VERSION 5.8 ;
BUSBITCHARS "[]" ;
DIVIDERCHAR "/" ;
UNITS
    DATABASE MICRONS 1000 ;
END UNITS

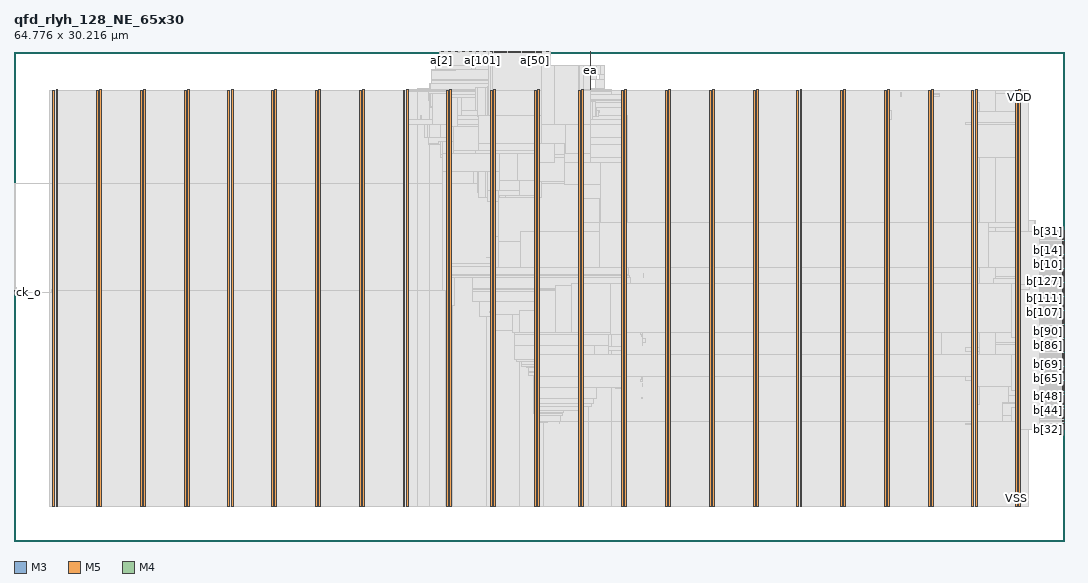
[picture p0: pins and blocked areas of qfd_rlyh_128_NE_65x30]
MACRO qfd_rlyh_128_NE_65x30
  FOREIGN qfd_rlyh_128_NE_65x30 0 0 ;
  CLASS BLOCK ;
  SIZE 64.776 BY 30.216 ;
  PIN a[0]
    DIRECTION INPUT ;
    USE SIGNAL ;
    PORT
      LAYER M3 ;
        RECT  26.244 30.179 26.262 30.216 ;
    END
  END a[0]
  PIN a[100]
    DIRECTION INPUT ;
    USE SIGNAL ;
    PORT
      LAYER M3 ;
        RECT  28.836 30.179 28.854 30.216 ;
    END
  END a[100]
  PIN a[101]
    DIRECTION INPUT ;
    USE SIGNAL ;
    PORT
      LAYER M3 ;
        RECT  28.908 30.179 28.926 30.216 ;
    END
  END a[101]
  PIN a[102]
    DIRECTION INPUT ;
    USE SIGNAL ;
    PORT
      LAYER M3 ;
        RECT  28.98 30.179 28.998 30.216 ;
    END
  END a[102]
  PIN a[103]
    DIRECTION INPUT ;
    USE SIGNAL ;
    PORT
      LAYER M3 ;
        RECT  29.052 30.179 29.07 30.216 ;
    END
  END a[103]
  PIN a[104]
    DIRECTION INPUT ;
    USE SIGNAL ;
    PORT
      LAYER M3 ;
        RECT  29.124 30.179 29.142 30.216 ;
    END
  END a[104]
  PIN a[105]
    DIRECTION INPUT ;
    USE SIGNAL ;
    PORT
      LAYER M3 ;
        RECT  29.196 30.179 29.214 30.216 ;
    END
  END a[105]
  PIN a[106]
    DIRECTION INPUT ;
    USE SIGNAL ;
    PORT
      LAYER M3 ;
        RECT  29.268 30.179 29.286 30.216 ;
    END
  END a[106]
  PIN a[107]
    DIRECTION INPUT ;
    USE SIGNAL ;
    PORT
      LAYER M3 ;
        RECT  29.34 30.179 29.358 30.216 ;
    END
  END a[107]
  PIN a[108]
    DIRECTION INPUT ;
    USE SIGNAL ;
    PORT
      LAYER M3 ;
        RECT  29.412 30.179 29.43 30.216 ;
    END
  END a[108]
  PIN a[109]
    DIRECTION INPUT ;
    USE SIGNAL ;
    PORT
      LAYER M3 ;
        RECT  29.484 30.179 29.502 30.216 ;
    END
  END a[109]
  PIN a[10]
    DIRECTION INPUT ;
    USE SIGNAL ;
    PORT
      LAYER M3 ;
        RECT  26.964 30.179 26.982 30.216 ;
    END
  END a[10]
  PIN a[110]
    DIRECTION INPUT ;
    USE SIGNAL ;
    PORT
      LAYER M3 ;
        RECT  29.556 30.179 29.574 30.216 ;
    END
  END a[110]
  PIN a[111]
    DIRECTION INPUT ;
    USE SIGNAL ;
    PORT
      LAYER M3 ;
        RECT  29.628 30.179 29.646 30.216 ;
    END
  END a[111]
  PIN a[112]
    DIRECTION INPUT ;
    USE SIGNAL ;
    PORT
      LAYER M3 ;
        RECT  29.7 30.179 29.718 30.216 ;
    END
  END a[112]
  PIN a[113]
    DIRECTION INPUT ;
    USE SIGNAL ;
    PORT
      LAYER M3 ;
        RECT  29.772 30.179 29.79 30.216 ;
    END
  END a[113]
  PIN a[114]
    DIRECTION INPUT ;
    USE SIGNAL ;
    PORT
      LAYER M3 ;
        RECT  29.844 30.179 29.862 30.216 ;
    END
  END a[114]
  PIN a[115]
    DIRECTION INPUT ;
    USE SIGNAL ;
    PORT
      LAYER M3 ;
        RECT  29.916 30.179 29.934 30.216 ;
    END
  END a[115]
  PIN a[116]
    DIRECTION INPUT ;
    USE SIGNAL ;
    PORT
      LAYER M3 ;
        RECT  29.988 30.179 30.006 30.216 ;
    END
  END a[116]
  PIN a[117]
    DIRECTION INPUT ;
    USE SIGNAL ;
    PORT
      LAYER M3 ;
        RECT  30.06 30.179 30.078 30.216 ;
    END
  END a[117]
  PIN a[118]
    DIRECTION INPUT ;
    USE SIGNAL ;
    PORT
      LAYER M3 ;
        RECT  30.132 30.179 30.15 30.216 ;
    END
  END a[118]
  PIN a[119]
    DIRECTION INPUT ;
    USE SIGNAL ;
    PORT
      LAYER M3 ;
        RECT  30.204 30.179 30.222 30.216 ;
    END
  END a[119]
  PIN a[11]
    DIRECTION INPUT ;
    USE SIGNAL ;
    PORT
      LAYER M3 ;
        RECT  27.036 30.179 27.054 30.216 ;
    END
  END a[11]
  PIN a[120]
    DIRECTION INPUT ;
    USE SIGNAL ;
    PORT
      LAYER M3 ;
        RECT  30.276 30.179 30.294 30.216 ;
    END
  END a[120]
  PIN a[121]
    DIRECTION INPUT ;
    USE SIGNAL ;
    PORT
      LAYER M3 ;
        RECT  30.348 30.179 30.366 30.216 ;
    END
  END a[121]
  PIN a[122]
    DIRECTION INPUT ;
    USE SIGNAL ;
    PORT
      LAYER M3 ;
        RECT  30.42 30.179 30.438 30.216 ;
    END
  END a[122]
  PIN a[123]
    DIRECTION INPUT ;
    USE SIGNAL ;
    PORT
      LAYER M3 ;
        RECT  30.492 30.179 30.51 30.216 ;
    END
  END a[123]
  PIN a[124]
    DIRECTION INPUT ;
    USE SIGNAL ;
    PORT
      LAYER M3 ;
        RECT  30.564 30.179 30.582 30.216 ;
    END
  END a[124]
  PIN a[125]
    DIRECTION INPUT ;
    USE SIGNAL ;
    PORT
      LAYER M3 ;
        RECT  30.636 30.179 30.654 30.216 ;
    END
  END a[125]
  PIN a[126]
    DIRECTION INPUT ;
    USE SIGNAL ;
    PORT
      LAYER M3 ;
        RECT  30.708 30.179 30.726 30.216 ;
    END
  END a[126]
  PIN a[127]
    DIRECTION INPUT ;
    USE SIGNAL ;
    PORT
      LAYER M3 ;
        RECT  30.78 30.179 30.798 30.216 ;
    END
  END a[127]
  PIN a[12]
    DIRECTION INPUT ;
    USE SIGNAL ;
    PORT
      LAYER M3 ;
        RECT  27.108 30.179 27.126 30.216 ;
    END
  END a[12]
  PIN a[13]
    DIRECTION INPUT ;
    USE SIGNAL ;
    PORT
      LAYER M3 ;
        RECT  27.18 30.179 27.198 30.216 ;
    END
  END a[13]
  PIN a[14]
    DIRECTION INPUT ;
    USE SIGNAL ;
    PORT
      LAYER M3 ;
        RECT  27.252 30.179 27.27 30.216 ;
    END
  END a[14]
  PIN a[15]
    DIRECTION INPUT ;
    USE SIGNAL ;
    PORT
      LAYER M3 ;
        RECT  27.324 30.179 27.342 30.216 ;
    END
  END a[15]
  PIN a[16]
    DIRECTION INPUT ;
    USE SIGNAL ;
    PORT
      LAYER M3 ;
        RECT  27.396 30.179 27.414 30.216 ;
    END
  END a[16]
  PIN a[17]
    DIRECTION INPUT ;
    USE SIGNAL ;
    PORT
      LAYER M3 ;
        RECT  27.468 30.179 27.486 30.216 ;
    END
  END a[17]
  PIN a[18]
    DIRECTION INPUT ;
    USE SIGNAL ;
    PORT
      LAYER M3 ;
        RECT  27.54 30.179 27.558 30.216 ;
    END
  END a[18]
  PIN a[19]
    DIRECTION INPUT ;
    USE SIGNAL ;
    PORT
      LAYER M3 ;
        RECT  27.612 30.179 27.63 30.216 ;
    END
  END a[19]
  PIN a[1]
    DIRECTION INPUT ;
    USE SIGNAL ;
    PORT
      LAYER M3 ;
        RECT  26.316 30.179 26.334 30.216 ;
    END
  END a[1]
  PIN a[20]
    DIRECTION INPUT ;
    USE SIGNAL ;
    PORT
      LAYER M3 ;
        RECT  27.684 30.179 27.702 30.216 ;
    END
  END a[20]
  PIN a[21]
    DIRECTION INPUT ;
    USE SIGNAL ;
    PORT
      LAYER M3 ;
        RECT  27.756 30.179 27.774 30.216 ;
    END
  END a[21]
  PIN a[22]
    DIRECTION INPUT ;
    USE SIGNAL ;
    PORT
      LAYER M3 ;
        RECT  27.828 30.179 27.846 30.216 ;
    END
  END a[22]
  PIN a[23]
    DIRECTION INPUT ;
    USE SIGNAL ;
    PORT
      LAYER M3 ;
        RECT  27.9 30.179 27.918 30.216 ;
    END
  END a[23]
  PIN a[24]
    DIRECTION INPUT ;
    USE SIGNAL ;
    PORT
      LAYER M3 ;
        RECT  27.972 30.179 27.99 30.216 ;
    END
  END a[24]
  PIN a[25]
    DIRECTION INPUT ;
    USE SIGNAL ;
    PORT
      LAYER M3 ;
        RECT  28.044 30.179 28.062 30.216 ;
    END
  END a[25]
  PIN a[26]
    DIRECTION INPUT ;
    USE SIGNAL ;
    PORT
      LAYER M3 ;
        RECT  28.116 30.179 28.134 30.216 ;
    END
  END a[26]
  PIN a[27]
    DIRECTION INPUT ;
    USE SIGNAL ;
    PORT
      LAYER M3 ;
        RECT  28.188 30.179 28.206 30.216 ;
    END
  END a[27]
  PIN a[28]
    DIRECTION INPUT ;
    USE SIGNAL ;
    PORT
      LAYER M3 ;
        RECT  28.26 30.179 28.278 30.216 ;
    END
  END a[28]
  PIN a[29]
    DIRECTION INPUT ;
    USE SIGNAL ;
    PORT
      LAYER M3 ;
        RECT  28.332 30.179 28.35 30.216 ;
    END
  END a[29]
  PIN a[2]
    DIRECTION INPUT ;
    USE SIGNAL ;
    PORT
      LAYER M3 ;
        RECT  26.388 30.179 26.406 30.216 ;
    END
  END a[2]
  PIN a[30]
    DIRECTION INPUT ;
    USE SIGNAL ;
    PORT
      LAYER M3 ;
        RECT  28.404 30.179 28.422 30.216 ;
    END
  END a[30]
  PIN a[31]
    DIRECTION INPUT ;
    USE SIGNAL ;
    PORT
      LAYER M3 ;
        RECT  28.476 30.179 28.494 30.216 ;
    END
  END a[31]
  PIN a[32]
    DIRECTION INPUT ;
    USE SIGNAL ;
    PORT
      LAYER M3 ;
        RECT  30.852 30.179 30.87 30.216 ;
    END
  END a[32]
  PIN a[33]
    DIRECTION INPUT ;
    USE SIGNAL ;
    PORT
      LAYER M3 ;
        RECT  30.924 30.179 30.942 30.216 ;
    END
  END a[33]
  PIN a[34]
    DIRECTION INPUT ;
    USE SIGNAL ;
    PORT
      LAYER M3 ;
        RECT  30.996 30.179 31.014 30.216 ;
    END
  END a[34]
  PIN a[35]
    DIRECTION INPUT ;
    USE SIGNAL ;
    PORT
      LAYER M3 ;
        RECT  31.068 30.179 31.086 30.216 ;
    END
  END a[35]
  PIN a[36]
    DIRECTION INPUT ;
    USE SIGNAL ;
    PORT
      LAYER M3 ;
        RECT  31.14 30.179 31.158 30.216 ;
    END
  END a[36]
  PIN a[37]
    DIRECTION INPUT ;
    USE SIGNAL ;
    PORT
      LAYER M3 ;
        RECT  31.212 30.179 31.23 30.216 ;
    END
  END a[37]
  PIN a[38]
    DIRECTION INPUT ;
    USE SIGNAL ;
    PORT
      LAYER M3 ;
        RECT  31.284 30.179 31.302 30.216 ;
    END
  END a[38]
  PIN a[39]
    DIRECTION INPUT ;
    USE SIGNAL ;
    PORT
      LAYER M3 ;
        RECT  31.356 30.179 31.374 30.216 ;
    END
  END a[39]
  PIN a[3]
    DIRECTION INPUT ;
    USE SIGNAL ;
    PORT
      LAYER M3 ;
        RECT  26.46 30.179 26.478 30.216 ;
    END
  END a[3]
  PIN a[40]
    DIRECTION INPUT ;
    USE SIGNAL ;
    PORT
      LAYER M3 ;
        RECT  31.428 30.179 31.446 30.216 ;
    END
  END a[40]
  PIN a[41]
    DIRECTION INPUT ;
    USE SIGNAL ;
    PORT
      LAYER M3 ;
        RECT  31.5 30.179 31.518 30.216 ;
    END
  END a[41]
  PIN a[42]
    DIRECTION INPUT ;
    USE SIGNAL ;
    PORT
      LAYER M3 ;
        RECT  31.572 30.179 31.59 30.216 ;
    END
  END a[42]
  PIN a[43]
    DIRECTION INPUT ;
    USE SIGNAL ;
    PORT
      LAYER M3 ;
        RECT  31.644 30.179 31.662 30.216 ;
    END
  END a[43]
  PIN a[44]
    DIRECTION INPUT ;
    USE SIGNAL ;
    PORT
      LAYER M3 ;
        RECT  31.716 30.179 31.734 30.216 ;
    END
  END a[44]
  PIN a[45]
    DIRECTION INPUT ;
    USE SIGNAL ;
    PORT
      LAYER M3 ;
        RECT  31.788 30.179 31.806 30.216 ;
    END
  END a[45]
  PIN a[46]
    DIRECTION INPUT ;
    USE SIGNAL ;
    PORT
      LAYER M3 ;
        RECT  31.86 30.179 31.878 30.216 ;
    END
  END a[46]
  PIN a[47]
    DIRECTION INPUT ;
    USE SIGNAL ;
    PORT
      LAYER M3 ;
        RECT  31.932 30.179 31.95 30.216 ;
    END
  END a[47]
  PIN a[48]
    DIRECTION INPUT ;
    USE SIGNAL ;
    PORT
      LAYER M3 ;
        RECT  32.004 30.179 32.022 30.216 ;
    END
  END a[48]
  PIN a[49]
    DIRECTION INPUT ;
    USE SIGNAL ;
    PORT
      LAYER M3 ;
        RECT  32.076 30.179 32.094 30.216 ;
    END
  END a[49]
  PIN a[4]
    DIRECTION INPUT ;
    USE SIGNAL ;
    PORT
      LAYER M3 ;
        RECT  26.532 30.179 26.55 30.216 ;
    END
  END a[4]
  PIN a[50]
    DIRECTION INPUT ;
    USE SIGNAL ;
    PORT
      LAYER M3 ;
        RECT  32.148 30.179 32.166 30.216 ;
    END
  END a[50]
  PIN a[51]
    DIRECTION INPUT ;
    USE SIGNAL ;
    PORT
      LAYER M3 ;
        RECT  32.22 30.179 32.238 30.216 ;
    END
  END a[51]
  PIN a[52]
    DIRECTION INPUT ;
    USE SIGNAL ;
    PORT
      LAYER M3 ;
        RECT  32.292 30.179 32.31 30.216 ;
    END
  END a[52]
  PIN a[53]
    DIRECTION INPUT ;
    USE SIGNAL ;
    PORT
      LAYER M3 ;
        RECT  32.364 30.179 32.382 30.216 ;
    END
  END a[53]
  PIN a[54]
    DIRECTION INPUT ;
    USE SIGNAL ;
    PORT
      LAYER M3 ;
        RECT  32.436 30.179 32.454 30.216 ;
    END
  END a[54]
  PIN a[55]
    DIRECTION INPUT ;
    USE SIGNAL ;
    PORT
      LAYER M3 ;
        RECT  32.508 30.179 32.526 30.216 ;
    END
  END a[55]
  PIN a[56]
    DIRECTION INPUT ;
    USE SIGNAL ;
    PORT
      LAYER M3 ;
        RECT  32.58 30.179 32.598 30.216 ;
    END
  END a[56]
  PIN a[57]
    DIRECTION INPUT ;
    USE SIGNAL ;
    PORT
      LAYER M3 ;
        RECT  32.652 30.179 32.67 30.216 ;
    END
  END a[57]
  PIN a[58]
    DIRECTION INPUT ;
    USE SIGNAL ;
    PORT
      LAYER M3 ;
        RECT  32.724 30.179 32.742 30.216 ;
    END
  END a[58]
  PIN a[59]
    DIRECTION INPUT ;
    USE SIGNAL ;
    PORT
      LAYER M3 ;
        RECT  32.796 30.179 32.814 30.216 ;
    END
  END a[59]
  PIN a[5]
    DIRECTION INPUT ;
    USE SIGNAL ;
    PORT
      LAYER M3 ;
        RECT  26.604 30.179 26.622 30.216 ;
    END
  END a[5]
  PIN a[60]
    DIRECTION INPUT ;
    USE SIGNAL ;
    PORT
      LAYER M3 ;
        RECT  32.868 30.179 32.886 30.216 ;
    END
  END a[60]
  PIN a[61]
    DIRECTION INPUT ;
    USE SIGNAL ;
    PORT
      LAYER M3 ;
        RECT  32.94 30.179 32.958 30.216 ;
    END
  END a[61]
  PIN a[62]
    DIRECTION INPUT ;
    USE SIGNAL ;
    PORT
      LAYER M3 ;
        RECT  33.012 30.179 33.03 30.216 ;
    END
  END a[62]
  PIN a[63]
    DIRECTION INPUT ;
    USE SIGNAL ;
    PORT
      LAYER M3 ;
        RECT  33.084 30.179 33.102 30.216 ;
    END
  END a[63]
  PIN a[64]
    DIRECTION INPUT ;
    USE SIGNAL ;
    PORT
      LAYER M5 ;
        RECT  29.52 30.132 29.544 30.216 ;
    END
  END a[64]
  PIN a[65]
    DIRECTION INPUT ;
    USE SIGNAL ;
    PORT
      LAYER M5 ;
        RECT  29.616 30.132 29.64 30.216 ;
    END
  END a[65]
  PIN a[66]
    DIRECTION INPUT ;
    USE SIGNAL ;
    PORT
      LAYER M5 ;
        RECT  29.712 30.132 29.736 30.216 ;
    END
  END a[66]
  PIN a[67]
    DIRECTION INPUT ;
    USE SIGNAL ;
    PORT
      LAYER M5 ;
        RECT  29.808 30.132 29.832 30.216 ;
    END
  END a[67]
  PIN a[68]
    DIRECTION INPUT ;
    USE SIGNAL ;
    PORT
      LAYER M5 ;
        RECT  29.904 30.132 29.928 30.216 ;
    END
  END a[68]
  PIN a[69]
    DIRECTION INPUT ;
    USE SIGNAL ;
    PORT
      LAYER M5 ;
        RECT  30 30.132 30.024 30.216 ;
    END
  END a[69]
  PIN a[6]
    DIRECTION INPUT ;
    USE SIGNAL ;
    PORT
      LAYER M3 ;
        RECT  26.676 30.179 26.694 30.216 ;
    END
  END a[6]
  PIN a[70]
    DIRECTION INPUT ;
    USE SIGNAL ;
    PORT
      LAYER M5 ;
        RECT  30.096 30.132 30.12 30.216 ;
    END
  END a[70]
  PIN a[71]
    DIRECTION INPUT ;
    USE SIGNAL ;
    PORT
      LAYER M5 ;
        RECT  30.192 30.132 30.216 30.216 ;
    END
  END a[71]
  PIN a[72]
    DIRECTION INPUT ;
    USE SIGNAL ;
    PORT
      LAYER M5 ;
        RECT  30.288 30.132 30.312 30.216 ;
    END
  END a[72]
  PIN a[73]
    DIRECTION INPUT ;
    USE SIGNAL ;
    PORT
      LAYER M5 ;
        RECT  30.384 30.132 30.408 30.216 ;
    END
  END a[73]
  PIN a[74]
    DIRECTION INPUT ;
    USE SIGNAL ;
    PORT
      LAYER M5 ;
        RECT  30.48 30.132 30.504 30.216 ;
    END
  END a[74]
  PIN a[75]
    DIRECTION INPUT ;
    USE SIGNAL ;
    PORT
      LAYER M5 ;
        RECT  30.576 30.132 30.6 30.216 ;
    END
  END a[75]
  PIN a[76]
    DIRECTION INPUT ;
    USE SIGNAL ;
    PORT
      LAYER M5 ;
        RECT  30.672 30.132 30.696 30.216 ;
    END
  END a[76]
  PIN a[77]
    DIRECTION INPUT ;
    USE SIGNAL ;
    PORT
      LAYER M5 ;
        RECT  30.768 30.132 30.792 30.216 ;
    END
  END a[77]
  PIN a[78]
    DIRECTION INPUT ;
    USE SIGNAL ;
    PORT
      LAYER M5 ;
        RECT  30.864 30.132 30.888 30.216 ;
    END
  END a[78]
  PIN a[79]
    DIRECTION INPUT ;
    USE SIGNAL ;
    PORT
      LAYER M5 ;
        RECT  30.96 30.132 30.984 30.216 ;
    END
  END a[79]
  PIN a[7]
    DIRECTION INPUT ;
    USE SIGNAL ;
    PORT
      LAYER M3 ;
        RECT  26.748 30.179 26.766 30.216 ;
    END
  END a[7]
  PIN a[80]
    DIRECTION INPUT ;
    USE SIGNAL ;
    PORT
      LAYER M5 ;
        RECT  31.056 30.132 31.08 30.216 ;
    END
  END a[80]
  PIN a[81]
    DIRECTION INPUT ;
    USE SIGNAL ;
    PORT
      LAYER M5 ;
        RECT  31.152 30.132 31.176 30.216 ;
    END
  END a[81]
  PIN a[82]
    DIRECTION INPUT ;
    USE SIGNAL ;
    PORT
      LAYER M5 ;
        RECT  31.248 30.132 31.272 30.216 ;
    END
  END a[82]
  PIN a[83]
    DIRECTION INPUT ;
    USE SIGNAL ;
    PORT
      LAYER M5 ;
        RECT  31.344 30.132 31.368 30.216 ;
    END
  END a[83]
  PIN a[84]
    DIRECTION INPUT ;
    USE SIGNAL ;
    PORT
      LAYER M5 ;
        RECT  31.44 30.132 31.464 30.216 ;
    END
  END a[84]
  PIN a[85]
    DIRECTION INPUT ;
    USE SIGNAL ;
    PORT
      LAYER M5 ;
        RECT  31.536 30.132 31.56 30.216 ;
    END
  END a[85]
  PIN a[86]
    DIRECTION INPUT ;
    USE SIGNAL ;
    PORT
      LAYER M5 ;
        RECT  31.632 30.132 31.656 30.216 ;
    END
  END a[86]
  PIN a[87]
    DIRECTION INPUT ;
    USE SIGNAL ;
    PORT
      LAYER M5 ;
        RECT  31.728 30.132 31.752 30.216 ;
    END
  END a[87]
  PIN a[88]
    DIRECTION INPUT ;
    USE SIGNAL ;
    PORT
      LAYER M5 ;
        RECT  31.824 30.132 31.848 30.216 ;
    END
  END a[88]
  PIN a[89]
    DIRECTION INPUT ;
    USE SIGNAL ;
    PORT
      LAYER M5 ;
        RECT  31.92 30.132 31.944 30.216 ;
    END
  END a[89]
  PIN a[8]
    DIRECTION INPUT ;
    USE SIGNAL ;
    PORT
      LAYER M3 ;
        RECT  26.82 30.179 26.838 30.216 ;
    END
  END a[8]
  PIN a[90]
    DIRECTION INPUT ;
    USE SIGNAL ;
    PORT
      LAYER M5 ;
        RECT  32.016 30.132 32.04 30.216 ;
    END
  END a[90]
  PIN a[91]
    DIRECTION INPUT ;
    USE SIGNAL ;
    PORT
      LAYER M5 ;
        RECT  32.112 30.132 32.136 30.216 ;
    END
  END a[91]
  PIN a[92]
    DIRECTION INPUT ;
    USE SIGNAL ;
    PORT
      LAYER M5 ;
        RECT  32.208 30.132 32.232 30.216 ;
    END
  END a[92]
  PIN a[93]
    DIRECTION INPUT ;
    USE SIGNAL ;
    PORT
      LAYER M5 ;
        RECT  32.304 30.132 32.328 30.216 ;
    END
  END a[93]
  PIN a[94]
    DIRECTION INPUT ;
    USE SIGNAL ;
    PORT
      LAYER M5 ;
        RECT  32.4 30.132 32.424 30.216 ;
    END
  END a[94]
  PIN a[95]
    DIRECTION INPUT ;
    USE SIGNAL ;
    PORT
      LAYER M5 ;
        RECT  32.496 30.132 32.52 30.216 ;
    END
  END a[95]
  PIN a[96]
    DIRECTION INPUT ;
    USE SIGNAL ;
    PORT
      LAYER M3 ;
        RECT  28.548 30.179 28.566 30.216 ;
    END
  END a[96]
  PIN a[97]
    DIRECTION INPUT ;
    USE SIGNAL ;
    PORT
      LAYER M3 ;
        RECT  28.62 30.179 28.638 30.216 ;
    END
  END a[97]
  PIN a[98]
    DIRECTION INPUT ;
    USE SIGNAL ;
    PORT
      LAYER M3 ;
        RECT  28.692 30.179 28.71 30.216 ;
    END
  END a[98]
  PIN a[99]
    DIRECTION INPUT ;
    USE SIGNAL ;
    PORT
      LAYER M3 ;
        RECT  28.764 30.179 28.782 30.216 ;
    END
  END a[99]
  PIN a[9]
    DIRECTION INPUT ;
    USE SIGNAL ;
    PORT
      LAYER M3 ;
        RECT  26.892 30.179 26.91 30.216 ;
    END
  END a[9]
  PIN b[0]
    DIRECTION OUTPUT ;
    USE SIGNAL ;
    PORT
      LAYER M4 ;
        RECT  64.692 16.08 64.776 16.104 ;
    END
  END b[0]
  PIN b[100]
    DIRECTION OUTPUT ;
    USE SIGNAL ;
    PORT
      LAYER M4 ;
        RECT  64.692 13.392 64.776 13.416 ;
    END
  END b[100]
  PIN b[101]
    DIRECTION OUTPUT ;
    USE SIGNAL ;
    PORT
      LAYER M4 ;
        RECT  64.692 13.488 64.776 13.512 ;
    END
  END b[101]
  PIN b[102]
    DIRECTION OUTPUT ;
    USE SIGNAL ;
    PORT
      LAYER M4 ;
        RECT  64.692 13.584 64.776 13.608 ;
    END
  END b[102]
  PIN b[103]
    DIRECTION OUTPUT ;
    USE SIGNAL ;
    PORT
      LAYER M4 ;
        RECT  64.692 13.68 64.776 13.704 ;
    END
  END b[103]
  PIN b[104]
    DIRECTION OUTPUT ;
    USE SIGNAL ;
    PORT
      LAYER M4 ;
        RECT  64.692 13.776 64.776 13.8 ;
    END
  END b[104]
  PIN b[105]
    DIRECTION OUTPUT ;
    USE SIGNAL ;
    PORT
      LAYER M4 ;
        RECT  64.692 13.872 64.776 13.896 ;
    END
  END b[105]
  PIN b[106]
    DIRECTION OUTPUT ;
    USE SIGNAL ;
    PORT
      LAYER M4 ;
        RECT  64.692 13.968 64.776 13.992 ;
    END
  END b[106]
  PIN b[107]
    DIRECTION OUTPUT ;
    USE SIGNAL ;
    PORT
      LAYER M4 ;
        RECT  64.692 14.064 64.776 14.088 ;
    END
  END b[107]
  PIN b[108]
    DIRECTION OUTPUT ;
    USE SIGNAL ;
    PORT
      LAYER M4 ;
        RECT  64.692 14.16 64.776 14.184 ;
    END
  END b[108]
  PIN b[109]
    DIRECTION OUTPUT ;
    USE SIGNAL ;
    PORT
      LAYER M4 ;
        RECT  64.692 14.256 64.776 14.28 ;
    END
  END b[109]
  PIN b[10]
    DIRECTION OUTPUT ;
    USE SIGNAL ;
    PORT
      LAYER M4 ;
        RECT  64.692 17.04 64.776 17.064 ;
    END
  END b[10]
  PIN b[110]
    DIRECTION OUTPUT ;
    USE SIGNAL ;
    PORT
      LAYER M4 ;
        RECT  64.692 14.352 64.776 14.376 ;
    END
  END b[110]
  PIN b[111]
    DIRECTION OUTPUT ;
    USE SIGNAL ;
    PORT
      LAYER M4 ;
        RECT  64.692 14.448 64.776 14.472 ;
    END
  END b[111]
  PIN b[112]
    DIRECTION OUTPUT ;
    USE SIGNAL ;
    PORT
      LAYER M4 ;
        RECT  64.692 14.544 64.776 14.568 ;
    END
  END b[112]
  PIN b[113]
    DIRECTION OUTPUT ;
    USE SIGNAL ;
    PORT
      LAYER M4 ;
        RECT  64.692 14.64 64.776 14.664 ;
    END
  END b[113]
  PIN b[114]
    DIRECTION OUTPUT ;
    USE SIGNAL ;
    PORT
      LAYER M4 ;
        RECT  64.692 14.736 64.776 14.76 ;
    END
  END b[114]
  PIN b[115]
    DIRECTION OUTPUT ;
    USE SIGNAL ;
    PORT
      LAYER M4 ;
        RECT  64.692 14.832 64.776 14.856 ;
    END
  END b[115]
  PIN b[116]
    DIRECTION OUTPUT ;
    USE SIGNAL ;
    PORT
      LAYER M4 ;
        RECT  64.692 14.928 64.776 14.952 ;
    END
  END b[116]
  PIN b[117]
    DIRECTION OUTPUT ;
    USE SIGNAL ;
    PORT
      LAYER M4 ;
        RECT  64.692 15.024 64.776 15.048 ;
    END
  END b[117]
  PIN b[118]
    DIRECTION OUTPUT ;
    USE SIGNAL ;
    PORT
      LAYER M4 ;
        RECT  64.692 15.12 64.776 15.144 ;
    END
  END b[118]
  PIN b[119]
    DIRECTION OUTPUT ;
    USE SIGNAL ;
    PORT
      LAYER M4 ;
        RECT  64.692 15.216 64.776 15.24 ;
    END
  END b[119]
  PIN b[11]
    DIRECTION OUTPUT ;
    USE SIGNAL ;
    PORT
      LAYER M4 ;
        RECT  64.692 17.136 64.776 17.16 ;
    END
  END b[11]
  PIN b[120]
    DIRECTION OUTPUT ;
    USE SIGNAL ;
    PORT
      LAYER M4 ;
        RECT  64.692 15.312 64.776 15.336 ;
    END
  END b[120]
  PIN b[121]
    DIRECTION OUTPUT ;
    USE SIGNAL ;
    PORT
      LAYER M4 ;
        RECT  64.692 15.408 64.776 15.432 ;
    END
  END b[121]
  PIN b[122]
    DIRECTION OUTPUT ;
    USE SIGNAL ;
    PORT
      LAYER M4 ;
        RECT  64.692 15.504 64.776 15.528 ;
    END
  END b[122]
  PIN b[123]
    DIRECTION OUTPUT ;
    USE SIGNAL ;
    PORT
      LAYER M4 ;
        RECT  64.692 15.6 64.776 15.624 ;
    END
  END b[123]
  PIN b[124]
    DIRECTION OUTPUT ;
    USE SIGNAL ;
    PORT
      LAYER M4 ;
        RECT  64.692 15.696 64.776 15.72 ;
    END
  END b[124]
  PIN b[125]
    DIRECTION OUTPUT ;
    USE SIGNAL ;
    PORT
      LAYER M4 ;
        RECT  64.692 15.792 64.776 15.816 ;
    END
  END b[125]
  PIN b[126]
    DIRECTION OUTPUT ;
    USE SIGNAL ;
    PORT
      LAYER M4 ;
        RECT  64.692 15.888 64.776 15.912 ;
    END
  END b[126]
  PIN b[127]
    DIRECTION OUTPUT ;
    USE SIGNAL ;
    PORT
      LAYER M4 ;
        RECT  64.692 15.984 64.776 16.008 ;
    END
  END b[127]
  PIN b[12]
    DIRECTION OUTPUT ;
    USE SIGNAL ;
    PORT
      LAYER M4 ;
        RECT  64.692 17.232 64.776 17.256 ;
    END
  END b[12]
  PIN b[13]
    DIRECTION OUTPUT ;
    USE SIGNAL ;
    PORT
      LAYER M4 ;
        RECT  64.692 17.328 64.776 17.352 ;
    END
  END b[13]
  PIN b[14]
    DIRECTION OUTPUT ;
    USE SIGNAL ;
    PORT
      LAYER M4 ;
        RECT  64.692 17.424 64.776 17.448 ;
    END
  END b[14]
  PIN b[15]
    DIRECTION OUTPUT ;
    USE SIGNAL ;
    PORT
      LAYER M4 ;
        RECT  64.692 17.52 64.776 17.544 ;
    END
  END b[15]
  PIN b[16]
    DIRECTION OUTPUT ;
    USE SIGNAL ;
    PORT
      LAYER M4 ;
        RECT  64.692 17.616 64.776 17.64 ;
    END
  END b[16]
  PIN b[17]
    DIRECTION OUTPUT ;
    USE SIGNAL ;
    PORT
      LAYER M4 ;
        RECT  64.692 17.712 64.776 17.736 ;
    END
  END b[17]
  PIN b[18]
    DIRECTION OUTPUT ;
    USE SIGNAL ;
    PORT
      LAYER M4 ;
        RECT  64.692 17.808 64.776 17.832 ;
    END
  END b[18]
  PIN b[19]
    DIRECTION OUTPUT ;
    USE SIGNAL ;
    PORT
      LAYER M4 ;
        RECT  64.692 17.904 64.776 17.928 ;
    END
  END b[19]
  PIN b[1]
    DIRECTION OUTPUT ;
    USE SIGNAL ;
    PORT
      LAYER M4 ;
        RECT  64.692 16.176 64.776 16.2 ;
    END
  END b[1]
  PIN b[20]
    DIRECTION OUTPUT ;
    USE SIGNAL ;
    PORT
      LAYER M4 ;
        RECT  64.692 18 64.776 18.024 ;
    END
  END b[20]
  PIN b[21]
    DIRECTION OUTPUT ;
    USE SIGNAL ;
    PORT
      LAYER M4 ;
        RECT  64.692 18.096 64.776 18.12 ;
    END
  END b[21]
  PIN b[22]
    DIRECTION OUTPUT ;
    USE SIGNAL ;
    PORT
      LAYER M4 ;
        RECT  64.692 18.192 64.776 18.216 ;
    END
  END b[22]
  PIN b[23]
    DIRECTION OUTPUT ;
    USE SIGNAL ;
    PORT
      LAYER M4 ;
        RECT  64.692 18.288 64.776 18.312 ;
    END
  END b[23]
  PIN b[24]
    DIRECTION OUTPUT ;
    USE SIGNAL ;
    PORT
      LAYER M4 ;
        RECT  64.692 18.384 64.776 18.408 ;
    END
  END b[24]
  PIN b[25]
    DIRECTION OUTPUT ;
    USE SIGNAL ;
    PORT
      LAYER M4 ;
        RECT  64.692 18.48 64.776 18.504 ;
    END
  END b[25]
  PIN b[26]
    DIRECTION OUTPUT ;
    USE SIGNAL ;
    PORT
      LAYER M4 ;
        RECT  64.692 18.576 64.776 18.6 ;
    END
  END b[26]
  PIN b[27]
    DIRECTION OUTPUT ;
    USE SIGNAL ;
    PORT
      LAYER M4 ;
        RECT  64.692 18.672 64.776 18.696 ;
    END
  END b[27]
  PIN b[28]
    DIRECTION OUTPUT ;
    USE SIGNAL ;
    PORT
      LAYER M4 ;
        RECT  64.692 18.768 64.776 18.792 ;
    END
  END b[28]
  PIN b[29]
    DIRECTION OUTPUT ;
    USE SIGNAL ;
    PORT
      LAYER M4 ;
        RECT  64.692 18.864 64.776 18.888 ;
    END
  END b[29]
  PIN b[2]
    DIRECTION OUTPUT ;
    USE SIGNAL ;
    PORT
      LAYER M4 ;
        RECT  64.692 16.272 64.776 16.296 ;
    END
  END b[2]
  PIN b[30]
    DIRECTION OUTPUT ;
    USE SIGNAL ;
    PORT
      LAYER M4 ;
        RECT  64.692 18.96 64.776 18.984 ;
    END
  END b[30]
  PIN b[31]
    DIRECTION OUTPUT ;
    USE SIGNAL ;
    PORT
      LAYER M4 ;
        RECT  64.692 19.056 64.776 19.08 ;
    END
  END b[31]
  PIN b[32]
    DIRECTION OUTPUT ;
    USE SIGNAL ;
    PORT
      LAYER M4 ;
        RECT  64.692 6.864 64.776 6.888 ;
    END
  END b[32]
  PIN b[33]
    DIRECTION OUTPUT ;
    USE SIGNAL ;
    PORT
      LAYER M4 ;
        RECT  64.692 6.96 64.776 6.984 ;
    END
  END b[33]
  PIN b[34]
    DIRECTION OUTPUT ;
    USE SIGNAL ;
    PORT
      LAYER M4 ;
        RECT  64.692 7.056 64.776 7.08 ;
    END
  END b[34]
  PIN b[35]
    DIRECTION OUTPUT ;
    USE SIGNAL ;
    PORT
      LAYER M4 ;
        RECT  64.692 7.152 64.776 7.176 ;
    END
  END b[35]
  PIN b[36]
    DIRECTION OUTPUT ;
    USE SIGNAL ;
    PORT
      LAYER M4 ;
        RECT  64.692 7.248 64.776 7.272 ;
    END
  END b[36]
  PIN b[37]
    DIRECTION OUTPUT ;
    USE SIGNAL ;
    PORT
      LAYER M4 ;
        RECT  64.692 7.344 64.776 7.368 ;
    END
  END b[37]
  PIN b[38]
    DIRECTION OUTPUT ;
    USE SIGNAL ;
    PORT
      LAYER M4 ;
        RECT  64.692 7.44 64.776 7.464 ;
    END
  END b[38]
  PIN b[39]
    DIRECTION OUTPUT ;
    USE SIGNAL ;
    PORT
      LAYER M4 ;
        RECT  64.692 7.536 64.776 7.56 ;
    END
  END b[39]
  PIN b[3]
    DIRECTION OUTPUT ;
    USE SIGNAL ;
    PORT
      LAYER M4 ;
        RECT  64.692 16.368 64.776 16.392 ;
    END
  END b[3]
  PIN b[40]
    DIRECTION OUTPUT ;
    USE SIGNAL ;
    PORT
      LAYER M4 ;
        RECT  64.692 7.632 64.776 7.656 ;
    END
  END b[40]
  PIN b[41]
    DIRECTION OUTPUT ;
    USE SIGNAL ;
    PORT
      LAYER M4 ;
        RECT  64.692 7.728 64.776 7.752 ;
    END
  END b[41]
  PIN b[42]
    DIRECTION OUTPUT ;
    USE SIGNAL ;
    PORT
      LAYER M4 ;
        RECT  64.692 7.824 64.776 7.848 ;
    END
  END b[42]
  PIN b[43]
    DIRECTION OUTPUT ;
    USE SIGNAL ;
    PORT
      LAYER M4 ;
        RECT  64.692 7.92 64.776 7.944 ;
    END
  END b[43]
  PIN b[44]
    DIRECTION OUTPUT ;
    USE SIGNAL ;
    PORT
      LAYER M4 ;
        RECT  64.692 8.016 64.776 8.04 ;
    END
  END b[44]
  PIN b[45]
    DIRECTION OUTPUT ;
    USE SIGNAL ;
    PORT
      LAYER M4 ;
        RECT  64.692 8.112 64.776 8.136 ;
    END
  END b[45]
  PIN b[46]
    DIRECTION OUTPUT ;
    USE SIGNAL ;
    PORT
      LAYER M4 ;
        RECT  64.692 8.208 64.776 8.232 ;
    END
  END b[46]
  PIN b[47]
    DIRECTION OUTPUT ;
    USE SIGNAL ;
    PORT
      LAYER M4 ;
        RECT  64.692 8.304 64.776 8.328 ;
    END
  END b[47]
  PIN b[48]
    DIRECTION OUTPUT ;
    USE SIGNAL ;
    PORT
      LAYER M4 ;
        RECT  64.692 8.4 64.776 8.424 ;
    END
  END b[48]
  PIN b[49]
    DIRECTION OUTPUT ;
    USE SIGNAL ;
    PORT
      LAYER M4 ;
        RECT  64.692 8.496 64.776 8.52 ;
    END
  END b[49]
  PIN b[4]
    DIRECTION OUTPUT ;
    USE SIGNAL ;
    PORT
      LAYER M4 ;
        RECT  64.692 16.464 64.776 16.488 ;
    END
  END b[4]
  PIN b[50]
    DIRECTION OUTPUT ;
    USE SIGNAL ;
    PORT
      LAYER M4 ;
        RECT  64.692 8.592 64.776 8.616 ;
    END
  END b[50]
  PIN b[51]
    DIRECTION OUTPUT ;
    USE SIGNAL ;
    PORT
      LAYER M4 ;
        RECT  64.692 8.688 64.776 8.712 ;
    END
  END b[51]
  PIN b[52]
    DIRECTION OUTPUT ;
    USE SIGNAL ;
    PORT
      LAYER M4 ;
        RECT  64.692 8.784 64.776 8.808 ;
    END
  END b[52]
  PIN b[53]
    DIRECTION OUTPUT ;
    USE SIGNAL ;
    PORT
      LAYER M4 ;
        RECT  64.692 8.88 64.776 8.904 ;
    END
  END b[53]
  PIN b[54]
    DIRECTION OUTPUT ;
    USE SIGNAL ;
    PORT
      LAYER M4 ;
        RECT  64.692 8.976 64.776 9 ;
    END
  END b[54]
  PIN b[55]
    DIRECTION OUTPUT ;
    USE SIGNAL ;
    PORT
      LAYER M4 ;
        RECT  64.692 9.072 64.776 9.096 ;
    END
  END b[55]
  PIN b[56]
    DIRECTION OUTPUT ;
    USE SIGNAL ;
    PORT
      LAYER M4 ;
        RECT  64.692 9.168 64.776 9.192 ;
    END
  END b[56]
  PIN b[57]
    DIRECTION OUTPUT ;
    USE SIGNAL ;
    PORT
      LAYER M4 ;
        RECT  64.692 9.264 64.776 9.288 ;
    END
  END b[57]
  PIN b[58]
    DIRECTION OUTPUT ;
    USE SIGNAL ;
    PORT
      LAYER M4 ;
        RECT  64.692 9.36 64.776 9.384 ;
    END
  END b[58]
  PIN b[59]
    DIRECTION OUTPUT ;
    USE SIGNAL ;
    PORT
      LAYER M4 ;
        RECT  64.692 9.456 64.776 9.48 ;
    END
  END b[59]
  PIN b[5]
    DIRECTION OUTPUT ;
    USE SIGNAL ;
    PORT
      LAYER M4 ;
        RECT  64.692 16.56 64.776 16.584 ;
    END
  END b[5]
  PIN b[60]
    DIRECTION OUTPUT ;
    USE SIGNAL ;
    PORT
      LAYER M4 ;
        RECT  64.692 9.552 64.776 9.576 ;
    END
  END b[60]
  PIN b[61]
    DIRECTION OUTPUT ;
    USE SIGNAL ;
    PORT
      LAYER M4 ;
        RECT  64.692 9.648 64.776 9.672 ;
    END
  END b[61]
  PIN b[62]
    DIRECTION OUTPUT ;
    USE SIGNAL ;
    PORT
      LAYER M4 ;
        RECT  64.692 9.744 64.776 9.768 ;
    END
  END b[62]
  PIN b[63]
    DIRECTION OUTPUT ;
    USE SIGNAL ;
    PORT
      LAYER M4 ;
        RECT  64.692 9.84 64.776 9.864 ;
    END
  END b[63]
  PIN b[64]
    DIRECTION OUTPUT ;
    USE SIGNAL ;
    PORT
      LAYER M4 ;
        RECT  64.692 9.936 64.776 9.96 ;
    END
  END b[64]
  PIN b[65]
    DIRECTION OUTPUT ;
    USE SIGNAL ;
    PORT
      LAYER M4 ;
        RECT  64.692 10.032 64.776 10.056 ;
    END
  END b[65]
  PIN b[66]
    DIRECTION OUTPUT ;
    USE SIGNAL ;
    PORT
      LAYER M4 ;
        RECT  64.692 10.128 64.776 10.152 ;
    END
  END b[66]
  PIN b[67]
    DIRECTION OUTPUT ;
    USE SIGNAL ;
    PORT
      LAYER M4 ;
        RECT  64.692 10.224 64.776 10.248 ;
    END
  END b[67]
  PIN b[68]
    DIRECTION OUTPUT ;
    USE SIGNAL ;
    PORT
      LAYER M4 ;
        RECT  64.692 10.32 64.776 10.344 ;
    END
  END b[68]
  PIN b[69]
    DIRECTION OUTPUT ;
    USE SIGNAL ;
    PORT
      LAYER M4 ;
        RECT  64.692 10.416 64.776 10.44 ;
    END
  END b[69]
  PIN b[6]
    DIRECTION OUTPUT ;
    USE SIGNAL ;
    PORT
      LAYER M4 ;
        RECT  64.692 16.656 64.776 16.68 ;
    END
  END b[6]
  PIN b[70]
    DIRECTION OUTPUT ;
    USE SIGNAL ;
    PORT
      LAYER M4 ;
        RECT  64.692 10.512 64.776 10.536 ;
    END
  END b[70]
  PIN b[71]
    DIRECTION OUTPUT ;
    USE SIGNAL ;
    PORT
      LAYER M4 ;
        RECT  64.692 10.608 64.776 10.632 ;
    END
  END b[71]
  PIN b[72]
    DIRECTION OUTPUT ;
    USE SIGNAL ;
    PORT
      LAYER M4 ;
        RECT  64.692 10.704 64.776 10.728 ;
    END
  END b[72]
  PIN b[73]
    DIRECTION OUTPUT ;
    USE SIGNAL ;
    PORT
      LAYER M4 ;
        RECT  64.692 10.8 64.776 10.824 ;
    END
  END b[73]
  PIN b[74]
    DIRECTION OUTPUT ;
    USE SIGNAL ;
    PORT
      LAYER M4 ;
        RECT  64.692 10.896 64.776 10.92 ;
    END
  END b[74]
  PIN b[75]
    DIRECTION OUTPUT ;
    USE SIGNAL ;
    PORT
      LAYER M4 ;
        RECT  64.692 10.992 64.776 11.016 ;
    END
  END b[75]
  PIN b[76]
    DIRECTION OUTPUT ;
    USE SIGNAL ;
    PORT
      LAYER M4 ;
        RECT  64.692 11.088 64.776 11.112 ;
    END
  END b[76]
  PIN b[77]
    DIRECTION OUTPUT ;
    USE SIGNAL ;
    PORT
      LAYER M4 ;
        RECT  64.692 11.184 64.776 11.208 ;
    END
  END b[77]
  PIN b[78]
    DIRECTION OUTPUT ;
    USE SIGNAL ;
    PORT
      LAYER M4 ;
        RECT  64.692 11.28 64.776 11.304 ;
    END
  END b[78]
  PIN b[79]
    DIRECTION OUTPUT ;
    USE SIGNAL ;
    PORT
      LAYER M4 ;
        RECT  64.692 11.376 64.776 11.4 ;
    END
  END b[79]
  PIN b[7]
    DIRECTION OUTPUT ;
    USE SIGNAL ;
    PORT
      LAYER M4 ;
        RECT  64.692 16.752 64.776 16.776 ;
    END
  END b[7]
  PIN b[80]
    DIRECTION OUTPUT ;
    USE SIGNAL ;
    PORT
      LAYER M4 ;
        RECT  64.692 11.472 64.776 11.496 ;
    END
  END b[80]
  PIN b[81]
    DIRECTION OUTPUT ;
    USE SIGNAL ;
    PORT
      LAYER M4 ;
        RECT  64.692 11.568 64.776 11.592 ;
    END
  END b[81]
  PIN b[82]
    DIRECTION OUTPUT ;
    USE SIGNAL ;
    PORT
      LAYER M4 ;
        RECT  64.692 11.664 64.776 11.688 ;
    END
  END b[82]
  PIN b[83]
    DIRECTION OUTPUT ;
    USE SIGNAL ;
    PORT
      LAYER M4 ;
        RECT  64.692 11.76 64.776 11.784 ;
    END
  END b[83]
  PIN b[84]
    DIRECTION OUTPUT ;
    USE SIGNAL ;
    PORT
      LAYER M4 ;
        RECT  64.692 11.856 64.776 11.88 ;
    END
  END b[84]
  PIN b[85]
    DIRECTION OUTPUT ;
    USE SIGNAL ;
    PORT
      LAYER M4 ;
        RECT  64.692 11.952 64.776 11.976 ;
    END
  END b[85]
  PIN b[86]
    DIRECTION OUTPUT ;
    USE SIGNAL ;
    PORT
      LAYER M4 ;
        RECT  64.692 12.048 64.776 12.072 ;
    END
  END b[86]
  PIN b[87]
    DIRECTION OUTPUT ;
    USE SIGNAL ;
    PORT
      LAYER M4 ;
        RECT  64.692 12.144 64.776 12.168 ;
    END
  END b[87]
  PIN b[88]
    DIRECTION OUTPUT ;
    USE SIGNAL ;
    PORT
      LAYER M4 ;
        RECT  64.692 12.24 64.776 12.264 ;
    END
  END b[88]
  PIN b[89]
    DIRECTION OUTPUT ;
    USE SIGNAL ;
    PORT
      LAYER M4 ;
        RECT  64.692 12.336 64.776 12.36 ;
    END
  END b[89]
  PIN b[8]
    DIRECTION OUTPUT ;
    USE SIGNAL ;
    PORT
      LAYER M4 ;
        RECT  64.692 16.848 64.776 16.872 ;
    END
  END b[8]
  PIN b[90]
    DIRECTION OUTPUT ;
    USE SIGNAL ;
    PORT
      LAYER M4 ;
        RECT  64.692 12.432 64.776 12.456 ;
    END
  END b[90]
  PIN b[91]
    DIRECTION OUTPUT ;
    USE SIGNAL ;
    PORT
      LAYER M4 ;
        RECT  64.692 12.528 64.776 12.552 ;
    END
  END b[91]
  PIN b[92]
    DIRECTION OUTPUT ;
    USE SIGNAL ;
    PORT
      LAYER M4 ;
        RECT  64.692 12.624 64.776 12.648 ;
    END
  END b[92]
  PIN b[93]
    DIRECTION OUTPUT ;
    USE SIGNAL ;
    PORT
      LAYER M4 ;
        RECT  64.692 12.72 64.776 12.744 ;
    END
  END b[93]
  PIN b[94]
    DIRECTION OUTPUT ;
    USE SIGNAL ;
    PORT
      LAYER M4 ;
        RECT  64.692 12.816 64.776 12.84 ;
    END
  END b[94]
  PIN b[95]
    DIRECTION OUTPUT ;
    USE SIGNAL ;
    PORT
      LAYER M4 ;
        RECT  64.692 12.912 64.776 12.936 ;
    END
  END b[95]
  PIN b[96]
    DIRECTION OUTPUT ;
    USE SIGNAL ;
    PORT
      LAYER M4 ;
        RECT  64.692 13.008 64.776 13.032 ;
    END
  END b[96]
  PIN b[97]
    DIRECTION OUTPUT ;
    USE SIGNAL ;
    PORT
      LAYER M4 ;
        RECT  64.692 13.104 64.776 13.128 ;
    END
  END b[97]
  PIN b[98]
    DIRECTION OUTPUT ;
    USE SIGNAL ;
    PORT
      LAYER M4 ;
        RECT  64.692 13.2 64.776 13.224 ;
    END
  END b[98]
  PIN b[99]
    DIRECTION OUTPUT ;
    USE SIGNAL ;
    PORT
      LAYER M4 ;
        RECT  64.692 13.296 64.776 13.32 ;
    END
  END b[99]
  PIN b[9]
    DIRECTION OUTPUT ;
    USE SIGNAL ;
    PORT
      LAYER M4 ;
        RECT  64.692 16.944 64.776 16.968 ;
    END
  END b[9]
  PIN ck_o
    DIRECTION OUTPUT ;
    USE SIGNAL ;
    PORT
      LAYER M4 ;
        RECT  0 15.312 0.084 15.336 ;
    END
  END ck_o
  PIN ckf
    DIRECTION INPUT ;
    USE SIGNAL ;
    PORT
      LAYER M4 ;
        RECT  0 15.408 0.084 15.432 ;
    END
  END ckf
  PIN ea
    DIRECTION INPUT ;
    USE SIGNAL ;
    PORT
      LAYER M5 ;
        RECT  35.568 30.132 35.592 30.216 ;
    END
    PORT
      LAYER M5 ;
        RECT  35.568 27.833 35.592 30.16 ;
    END
  END ea
  PIN eb
    DIRECTION OUTPUT ;
    USE SIGNAL ;
    PORT
      LAYER M4 ;
        RECT  64.692 19.152 64.776 19.176 ;
    END
  END eb
  PIN VDD
    DIRECTION INOUT ;
    USE POWER ;
    PORT
      LAYER M5 ;
        RECT  61.992 2.151 62.112 27.833 ;
        RECT  59.292 2.151 59.412 27.833 ;
        RECT  56.592 2.151 56.712 27.833 ;
        RECT  53.892 2.151 54.012 27.833 ;
        RECT  51.192 2.151 51.312 27.833 ;
        RECT  48.492 2.151 48.612 27.833 ;
        RECT  45.792 2.151 45.912 27.833 ;
        RECT  43.092 2.151 43.212 27.833 ;
        RECT  40.392 2.151 40.512 27.833 ;
        RECT  37.692 2.151 37.812 27.833 ;
        RECT  34.992 2.151 35.112 27.833 ;
        RECT  32.292 2.151 32.412 27.833 ;
        RECT  29.592 2.151 29.712 27.833 ;
        RECT  26.892 2.151 27.012 27.833 ;
        RECT  24.192 2.151 24.312 27.833 ;
        RECT  21.492 2.151 21.612 27.833 ;
        RECT  18.792 2.151 18.912 27.833 ;
        RECT  16.092 2.151 16.212 27.833 ;
        RECT  13.392 2.151 13.512 27.833 ;
        RECT  10.692 2.151 10.812 27.833 ;
        RECT  7.992 2.151 8.112 27.833 ;
        RECT  5.292 2.151 5.412 27.833 ;
        RECT  2.592 2.151 2.712 27.833 ;
    END
  END VDD
  PIN VSS
    DIRECTION INOUT ;
    USE GROUND ;
    PORT
      LAYER M5 ;
        RECT  61.8 2.137 61.92 27.819 ;
        RECT  59.1 2.137 59.22 27.819 ;
        RECT  56.4 2.137 56.52 27.819 ;
        RECT  53.7 2.137 53.82 27.819 ;
        RECT  51 2.137 51.12 27.819 ;
        RECT  48.3 2.137 48.42 27.819 ;
        RECT  45.6 2.137 45.72 27.819 ;
        RECT  42.9 2.137 43.02 27.819 ;
        RECT  40.2 2.137 40.32 27.819 ;
        RECT  37.5 2.137 37.62 27.819 ;
        RECT  34.8 2.137 34.92 27.819 ;
        RECT  32.1 2.137 32.22 27.819 ;
        RECT  29.4 2.137 29.52 27.819 ;
        RECT  26.7 2.137 26.82 27.819 ;
        RECT  24 2.137 24.12 27.819 ;
        RECT  21.3 2.137 21.42 27.819 ;
        RECT  18.6 2.137 18.72 27.819 ;
        RECT  15.9 2.137 16.02 27.819 ;
        RECT  13.2 2.137 13.32 27.819 ;
        RECT  10.5 2.137 10.62 27.819 ;
        RECT  7.8 2.137 7.92 27.819 ;
        RECT  5.1 2.137 5.22 27.819 ;
        RECT  2.4 2.137 2.52 27.819 ;
    END
  END VSS
  # OT_OBS_CLOSED layer=M5 d_um=1.536 added=9
  OBS
    LAYER RVTN ;
     RECT  2.16 2.16 62.586 2.295 ;
     RECT  2.16 2.565 62.586 2.835 ;
     RECT  2.16 3.105 62.586 3.375 ;
     RECT  2.16 3.645 62.586 3.915 ;
     RECT  2.16 4.185 62.586 4.455 ;
     RECT  2.16 4.725 62.586 4.995 ;
     RECT  2.16 5.265 62.586 5.535 ;
     RECT  2.16 5.805 62.586 6.075 ;
     RECT  2.16 6.345 62.586 6.615 ;
     RECT  2.16 6.885 62.586 7.155 ;
     RECT  2.16 7.425 62.586 7.695 ;
     RECT  2.16 7.965 62.586 8.235 ;
     RECT  2.16 8.505 62.586 8.775 ;
     RECT  2.16 9.045 62.586 9.315 ;
     RECT  2.16 9.585 62.586 9.855 ;
     RECT  2.16 10.125 62.586 10.395 ;
     RECT  2.16 10.665 62.586 10.935 ;
     RECT  2.16 11.205 62.586 11.475 ;
     RECT  2.16 11.745 62.586 12.015 ;
     RECT  2.16 12.285 62.586 12.555 ;
     RECT  2.16 12.825 62.586 13.095 ;
     RECT  2.16 13.365 62.586 13.635 ;
     RECT  2.16 13.905 62.586 14.175 ;
     RECT  2.16 14.445 62.586 14.715 ;
     RECT  2.16 14.985 62.586 15.255 ;
     RECT  2.16 15.525 62.586 15.795 ;
     RECT  2.16 16.065 62.586 16.335 ;
     RECT  2.16 16.605 62.586 16.875 ;
     RECT  2.16 17.145 62.586 17.415 ;
     RECT  2.16 17.685 62.586 17.955 ;
     RECT  2.16 18.225 62.586 18.495 ;
     RECT  2.16 18.765 62.586 19.035 ;
     RECT  2.16 19.305 62.586 19.575 ;
     RECT  2.16 19.845 62.586 20.115 ;
     RECT  2.16 20.385 62.586 20.655 ;
     RECT  2.16 20.925 62.586 21.195 ;
     RECT  2.16 21.465 62.586 21.735 ;
     RECT  2.16 22.005 62.586 22.275 ;
     RECT  2.16 22.545 62.586 22.815 ;
     RECT  2.16 23.085 62.586 23.355 ;
     RECT  2.16 23.625 62.586 23.895 ;
     RECT  2.16 24.165 62.586 24.435 ;
     RECT  2.16 24.705 62.586 24.975 ;
     RECT  2.16 25.245 62.586 25.515 ;
     RECT  2.16 25.785 62.586 26.055 ;
     RECT  2.16 26.325 62.586 26.595 ;
     RECT  2.16 26.865 62.586 27.135 ;
     RECT  2.16 27.405 62.586 27.675 ;
    LAYER RVTP ;
     RECT  2.16 2.295 62.586 2.565 ;
     RECT  2.16 2.835 62.586 3.105 ;
     RECT  2.16 3.375 62.586 3.645 ;
     RECT  2.16 3.915 62.586 4.185 ;
     RECT  2.16 4.455 62.586 4.725 ;
     RECT  2.16 4.995 62.586 5.265 ;
     RECT  2.16 5.535 62.586 5.805 ;
     RECT  2.16 6.075 62.586 6.345 ;
     RECT  2.16 6.615 62.586 6.885 ;
     RECT  2.16 7.155 62.586 7.425 ;
     RECT  2.16 7.695 62.586 7.965 ;
     RECT  2.16 8.235 62.586 8.505 ;
     RECT  2.16 8.775 62.586 9.045 ;
     RECT  2.16 9.315 62.586 9.585 ;
     RECT  2.16 9.855 62.586 10.125 ;
     RECT  2.16 10.395 62.586 10.665 ;
     RECT  2.16 10.935 62.586 11.205 ;
     RECT  2.16 11.475 62.586 11.745 ;
     RECT  2.16 12.015 62.586 12.285 ;
     RECT  2.16 12.555 62.586 12.825 ;
     RECT  2.16 13.095 62.586 13.365 ;
     RECT  2.16 13.635 62.586 13.905 ;
     RECT  2.16 14.175 62.586 14.445 ;
     RECT  2.16 14.715 62.586 14.985 ;
     RECT  2.16 15.255 62.586 15.525 ;
     RECT  2.16 15.795 62.586 16.065 ;
     RECT  2.16 16.335 62.586 16.605 ;
     RECT  2.16 16.875 62.586 17.145 ;
     RECT  2.16 17.415 62.586 17.685 ;
     RECT  2.16 17.955 62.586 18.225 ;
     RECT  2.16 18.495 62.586 18.765 ;
     RECT  2.16 19.035 62.586 19.305 ;
     RECT  2.16 19.575 62.586 19.845 ;
     RECT  2.16 20.115 62.586 20.385 ;
     RECT  2.16 20.655 62.586 20.925 ;
     RECT  2.16 21.195 62.586 21.465 ;
     RECT  2.16 21.735 62.586 22.005 ;
     RECT  2.16 22.275 62.586 22.545 ;
     RECT  2.16 22.815 62.586 23.085 ;
     RECT  2.16 23.355 62.586 23.625 ;
     RECT  2.16 23.895 62.586 24.165 ;
     RECT  2.16 24.435 62.586 24.705 ;
     RECT  2.16 24.975 62.586 25.245 ;
     RECT  2.16 25.515 62.586 25.785 ;
     RECT  2.16 26.055 62.586 26.325 ;
     RECT  2.16 26.595 62.586 26.865 ;
     RECT  2.16 27.135 62.586 27.405 ;
     RECT  2.16 27.675 62.586 27.81 ;
    LAYER M1 ;
     RECT  2.16 2.151 62.586 27.819 ;
    LAYER M2 ;
     RECT  2.16 2.151 24.907 27.819 ;
     RECT  24.907 2.151 25.663 27.936 ;
     RECT  25.987 29.34 26.347 29.358 ;
     RECT  26.347 29.34 26.419 30.096 ;
     RECT  25.663 2.151 26.635 28.206 ;
     RECT  26.635 2.151 27.059 28.512 ;
     RECT  26.419 29.34 28.291 30.168 ;
     RECT  28.291 29.034 28.391 30.168 ;
     RECT  28.391 29.268 28.823 30.168 ;
     RECT  27.059 2.151 29.147 28.206 ;
     RECT  29.147 2.151 29.435 27.864 ;
     RECT  28.823 29.916 29.579 30.168 ;
     RECT  29.579 29.961 30.695 30.168 ;
     RECT  29.435 2.151 31.171 27.819 ;
     RECT  30.695 30.006 31.927 30.168 ;
     RECT  31.927 29.268 31.999 30.168 ;
     RECT  31.999 28.962 32.315 30.168 ;
     RECT  31.171 2.151 32.431 27.864 ;
     RECT  32.431 2.151 32.647 27.9 ;
     RECT  32.315 29.034 32.891 30.168 ;
     RECT  32.891 30.15 32.999 30.168 ;
     RECT  32.891 29.034 35.159 29.358 ;
     RECT  32.647 2.151 35.411 27.936 ;
     RECT  35.159 29.34 36.455 29.358 ;
     RECT  35.411 2.151 36.851 27.864 ;
     RECT  36.851 2.151 62.586 27.819 ;
     RECT  62.586 7.164 62.987 19.764 ;
     RECT  62.987 7.164 63.311 19.224 ;
     RECT  63.311 7.164 63.347 9.54 ;
     RECT  63.311 10.332 63.347 15.174 ;
     RECT  63.347 7.164 63.887 8.334 ;
     RECT  63.347 9.216 63.887 9.54 ;
     RECT  63.347 10.332 63.887 13.734 ;
     RECT  63.347 14.652 63.887 15.174 ;
     RECT  63.311 16.002 63.887 18.756 ;
     RECT  63.887 8.136 63.923 8.154 ;
     RECT  63.887 9.288 63.923 9.414 ;
     RECT  63.887 12.222 63.923 12.24 ;
     RECT  63.887 13.302 63.923 13.428 ;
     RECT  63.887 14.958 63.923 14.976 ;
     RECT  63.887 16.002 63.923 18.594 ;
     RECT  63.923 9.396 63.959 9.414 ;
     RECT  63.923 16.956 63.959 16.974 ;
     RECT  63.923 17.766 64.607 17.784 ;
     RECT  63.923 13.41 64.651 13.428 ;
     RECT  64.615 9.486 64.751 9.504 ;
     RECT  64.651 10.791 64.751 10.809 ;
     RECT  64.651 13.41 64.751 14.13 ;
     RECT  64.651 15.426 64.751 15.894 ;
     RECT  64.651 17.811 64.751 17.829 ;
    LAYER M3 ;
     RECT  2.415 2.143 2.505 2.413 ;
     RECT  5.115 2.143 5.205 2.413 ;
     RECT  7.815 2.143 7.905 2.413 ;
     RECT  10.515 2.143 10.605 2.413 ;
     RECT  13.215 2.143 13.305 2.413 ;
     RECT  15.915 2.143 16.005 2.413 ;
     RECT  18.615 2.143 18.705 2.413 ;
     RECT  21.315 2.143 21.405 2.413 ;
     RECT  24.015 2.143 24.105 2.413 ;
     RECT  26.715 2.143 26.805 2.413 ;
     RECT  29.415 2.143 29.505 2.413 ;
     RECT  32.115 2.143 32.205 2.413 ;
     RECT  34.815 2.143 34.905 2.413 ;
     RECT  37.515 2.143 37.605 2.413 ;
     RECT  40.215 2.143 40.305 2.413 ;
     RECT  42.915 2.143 43.005 2.413 ;
     RECT  45.615 2.143 45.705 2.413 ;
     RECT  48.315 2.143 48.405 2.413 ;
     RECT  51.015 2.143 51.105 2.413 ;
     RECT  53.715 2.143 53.805 2.413 ;
     RECT  56.415 2.143 56.505 2.413 ;
     RECT  59.115 2.143 59.205 2.413 ;
     RECT  61.815 2.143 61.905 2.413 ;
     RECT  61.815 2.413 62.097 6.859 ;
     RECT  61.815 6.859 62.73 6.955 ;
     RECT  61.815 6.955 62.982 7.147 ;
     RECT  59.115 2.413 59.397 7.159 ;
     RECT  61.815 7.147 63.306 7.159 ;
     RECT  58.716 7.159 59.397 7.259 ;
     RECT  32.115 2.413 32.397 7.339 ;
     RECT  61.815 7.159 63.882 7.349 ;
     RECT  32.115 7.339 32.922 7.393 ;
     RECT  33.66 7.231 33.678 7.393 ;
     RECT  63.864 7.349 63.882 7.723 ;
     RECT  60.984 7.357 61.002 7.735 ;
     RECT  61.815 7.349 62.982 7.735 ;
     RECT  32.115 7.393 33.714 7.771 ;
     RECT  32.115 7.771 33.822 7.861 ;
     RECT  32.076 7.861 33.822 7.933 ;
     RECT  32.076 7.933 33.894 8.041 ;
     RECT  34.815 2.413 35.097 8.041 ;
     RECT  63.864 7.723 63.918 8.159 ;
     RECT  32.076 8.041 35.097 8.311 ;
     RECT  59.115 7.259 59.397 8.437 ;
     RECT  60.984 7.735 62.982 8.491 ;
     RECT  63.864 8.159 63.882 8.491 ;
     RECT  32.076 8.311 35.622 8.509 ;
     RECT  60.984 8.491 63.882 8.573 ;
     RECT  32.076 8.509 35.766 8.815 ;
     RECT  38.736 8.779 38.754 8.879 ;
     RECT  61.38 8.573 63.882 8.969 ;
     RECT  63.864 8.969 63.882 8.971 ;
     RECT  63.864 8.971 63.918 9.067 ;
     RECT  64.656 7.051 64.674 9.067 ;
     RECT  37.515 2.413 37.797 9.391 ;
     RECT  63.864 9.067 64.674 9.419 ;
     RECT  32.076 8.815 35.946 9.481 ;
     RECT  37.116 9.391 37.797 9.481 ;
     RECT  64.62 9.419 64.674 9.481 ;
     RECT  64.62 9.481 64.746 9.509 ;
     RECT  64.656 9.509 64.746 9.533 ;
     RECT  63.864 9.419 63.882 9.545 ;
     RECT  38.772 9.517 38.79 9.689 ;
     RECT  61.38 8.969 62.982 9.739 ;
     RECT  61.38 9.739 63.558 9.835 ;
     RECT  59.115 8.437 59.562 9.931 ;
     RECT  38.664 9.823 38.754 9.959 ;
     RECT  32.076 9.481 37.797 10.201 ;
     RECT  60.948 9.835 63.558 10.315 ;
     RECT  31.752 10.201 37.797 10.399 ;
     RECT  31.716 10.399 37.797 10.427 ;
     RECT  38.7 9.959 38.754 10.435 ;
     RECT  60.948 10.315 63.882 10.463 ;
     RECT  31.716 10.427 36.666 10.705 ;
     RECT  58.716 9.931 59.562 10.733 ;
     RECT  31.644 10.705 36.666 10.741 ;
     RECT  38.7 10.435 38.79 10.769 ;
     RECT  64.656 9.533 64.674 10.786 ;
     RECT  64.656 10.786 64.746 10.814 ;
     RECT  31.32 10.741 36.666 10.859 ;
     RECT  59.115 10.733 59.562 10.891 ;
     RECT  59.115 10.891 59.85 10.967 ;
     RECT  31.32 10.859 35.838 11.101 ;
     RECT  58.176 11.011 58.194 11.129 ;
     RECT  30.996 11.101 35.838 11.209 ;
     RECT  56.415 2.413 56.697 11.245 ;
     RECT  61.092 10.463 63.882 11.245 ;
     RECT  38.772 10.769 38.79 11.309 ;
     RECT  46.764 11.179 46.782 11.309 ;
     RECT  54.72 10.939 54.738 11.309 ;
     RECT  60.948 11.245 63.882 11.479 ;
     RECT  59.115 10.967 59.562 11.677 ;
     RECT  36.648 10.859 36.666 11.749 ;
     RECT  37.515 10.427 37.797 11.749 ;
     RECT  58.716 11.677 59.562 11.939 ;
     RECT  36.648 11.749 37.797 11.975 ;
     RECT  30.888 11.209 35.838 12.091 ;
     RECT  36.648 11.975 36.702 12.091 ;
     RECT  60.552 11.479 63.882 12.139 ;
     RECT  38.772 12.091 38.79 12.217 ;
     RECT  60.552 12.139 63.918 12.245 ;
     RECT  38.772 12.217 38.862 12.253 ;
     RECT  38.772 12.253 38.934 12.479 ;
     RECT  38.772 12.479 38.79 12.595 ;
     RECT  30.888 12.091 36.702 12.712 ;
     RECT  37.515 11.975 37.797 12.712 ;
     RECT  38.736 12.595 38.79 12.757 ;
     RECT  38.664 12.757 38.79 12.857 ;
     RECT  30.888 12.712 37.797 12.859 ;
     RECT  38.736 12.857 38.79 12.86 ;
     RECT  30.78 12.859 37.797 13.003 ;
     RECT  60.552 12.245 63.882 13.091 ;
     RECT  62.964 13.091 63.882 13.195 ;
     RECT  29.415 2.413 29.697 13.261 ;
     RECT  30.42 13.003 37.797 13.261 ;
     RECT  62.964 13.195 63.918 13.405 ;
     RECT  64.728 10.814 64.746 13.405 ;
     RECT  29.415 13.261 37.797 13.873 ;
     RECT  62.964 13.405 64.746 14.099 ;
     RECT  42.915 2.413 43.197 14.107 ;
     RECT  51.015 2.413 51.297 14.107 ;
     RECT  59.115 11.939 59.562 14.107 ;
     RECT  63.864 14.099 64.746 14.144 ;
     RECT  60.552 13.091 62.097 14.155 ;
     RECT  62.964 14.099 62.982 14.155 ;
     RECT  38.772 12.86 38.79 14.237 ;
     RECT  42.768 14.107 43.197 14.237 ;
     RECT  46.764 12.859 46.782 14.237 ;
     RECT  50.724 14.107 51.297 14.237 ;
     RECT  54.72 12.859 54.738 14.237 ;
     RECT  58.716 14.107 59.562 14.237 ;
     RECT  58.788 14.237 59.562 14.243 ;
     RECT  26.715 2.413 26.997 14.521 ;
     RECT  28.692 13.873 37.797 14.791 ;
     RECT  56.415 11.245 57.222 14.909 ;
     RECT  63.864 14.144 64.602 15.245 ;
     RECT  2.415 2.413 2.697 15.295 ;
     RECT  60.552 14.155 62.982 15.307 ;
     RECT  64.584 15.245 64.602 15.403 ;
     RECT  28.26 14.791 37.797 15.421 ;
     RECT  64.584 15.403 64.674 15.421 ;
     RECT  2.412 15.295 2.697 15.448 ;
     RECT  2.34 15.448 2.697 15.485 ;
     RECT  60.552 15.307 63.306 15.485 ;
     RECT  28.26 15.421 38.394 15.499 ;
     RECT  60.552 15.485 62.982 15.547 ;
     RECT  28.26 15.499 38.79 15.557 ;
     RECT  38.772 15.557 38.79 15.629 ;
     RECT  46.764 15.499 46.782 15.629 ;
     RECT  54.72 15.499 54.738 15.629 ;
     RECT  64.584 15.421 64.746 15.899 ;
     RECT  64.584 15.899 64.674 15.917 ;
     RECT  64.584 15.917 64.602 15.997 ;
     RECT  60.408 15.547 62.982 16.169 ;
     RECT  26.715 14.521 27.162 16.231 ;
     RECT  28.26 15.557 38.034 16.231 ;
     RECT  26.715 16.231 38.034 16.259 ;
     RECT  60.552 16.169 62.982 16.295 ;
     RECT  63.864 15.997 64.602 16.339 ;
     RECT  26.715 16.259 37.998 16.367 ;
     RECT  63.828 16.339 64.602 16.375 ;
     RECT  26.715 16.367 37.926 16.439 ;
     RECT  63.792 16.375 64.602 16.493 ;
     RECT  38.808 16.267 38.826 16.529 ;
     RECT  45.615 2.413 45.897 16.939 ;
     RECT  53.715 2.413 53.997 16.939 ;
     RECT  26.715 16.439 37.89 16.951 ;
     RECT  26.604 16.951 37.89 17.117 ;
     RECT  45.615 16.939 45.99 17.117 ;
     RECT  53.715 16.939 54.738 17.117 ;
     RECT  38.772 16.939 38.79 17.453 ;
     RECT  46.764 16.939 46.782 17.453 ;
     RECT  54.72 17.117 54.738 17.453 ;
     RECT  63.864 16.493 64.602 17.455 ;
     RECT  63.828 17.455 64.602 17.549 ;
     RECT  60.552 16.295 62.19 17.755 ;
     RECT  62.964 16.295 62.982 17.755 ;
     RECT  63.864 17.549 64.602 17.755 ;
     RECT  63.864 17.755 64.746 17.789 ;
     RECT  64.656 17.789 64.746 17.834 ;
     RECT  64.656 17.834 64.674 17.837 ;
     RECT  60.552 17.755 62.982 17.933 ;
     RECT  59.115 14.243 59.562 17.959 ;
     RECT  58.716 17.959 59.562 18.059 ;
     RECT  58.788 18.059 59.562 18.149 ;
     RECT  63.864 17.789 63.918 18.605 ;
     RECT  63.864 18.605 63.882 18.667 ;
     RECT  63.828 18.667 63.882 18.761 ;
     RECT  60.552 17.933 62.097 18.859 ;
     RECT  62.964 17.933 62.982 18.859 ;
     RECT  60.552 18.859 62.982 18.959 ;
     RECT  62.964 18.959 62.982 19.147 ;
     RECT  62.964 19.147 63.306 19.229 ;
     RECT  59.115 18.149 59.562 19.345 ;
     RECT  60.552 18.959 62.097 19.345 ;
     RECT  59.115 19.345 62.097 19.661 ;
     RECT  62.964 19.229 62.982 19.769 ;
     RECT  59.115 19.661 59.562 23.629 ;
     RECT  60.552 19.661 62.097 23.629 ;
     RECT  26.604 17.117 37.854 23.665 ;
     RECT  26.316 23.665 37.854 24.475 ;
     RECT  25.596 24.475 37.854 24.871 ;
     RECT  25.308 24.871 37.854 24.899 ;
     RECT  24.015 2.413 24.297 25.675 ;
     RECT  25.308 24.899 25.506 25.675 ;
     RECT  26.316 24.899 37.854 25.675 ;
     RECT  59.115 23.629 62.097 25.681 ;
     RECT  58.716 25.681 62.097 25.817 ;
     RECT  24.015 25.675 37.854 25.979 ;
     RECT  53.715 17.117 53.997 25.987 ;
     RECT  24.015 25.979 25.11 26.015 ;
     RECT  25.092 26.015 25.11 26.249 ;
     RECT  25.848 25.979 37.854 26.249 ;
     RECT  59.115 25.817 62.097 26.519 ;
     RECT  53.715 25.987 54.162 26.555 ;
     RECT  25.848 26.249 37.797 26.761 ;
     RECT  25.704 26.761 37.797 27.031 ;
     RECT  59.115 26.519 59.562 27.059 ;
     RECT  25.668 27.031 37.797 27.175 ;
     RECT  25.596 27.175 37.797 27.211 ;
     RECT  56.415 14.909 56.697 27.445 ;
     RECT  2.415 15.485 2.697 27.557 ;
     RECT  5.115 2.413 5.397 27.557 ;
     RECT  7.815 2.413 8.097 27.557 ;
     RECT  10.515 2.413 10.797 27.557 ;
     RECT  13.215 2.413 13.497 27.557 ;
     RECT  15.915 2.413 16.197 27.557 ;
     RECT  18.615 2.413 18.897 27.557 ;
     RECT  21.315 2.413 21.597 27.557 ;
     RECT  24.015 26.015 24.297 27.557 ;
     RECT  25.56 27.211 37.797 27.557 ;
     RECT  40.215 2.413 40.497 27.557 ;
     RECT  42.915 14.237 43.197 27.557 ;
     RECT  45.615 17.117 45.897 27.557 ;
     RECT  48.315 2.413 48.597 27.557 ;
     RECT  51.015 14.237 51.297 27.557 ;
     RECT  53.715 26.555 53.997 27.557 ;
     RECT  56.415 27.445 57.114 27.557 ;
     RECT  59.115 27.059 59.397 27.557 ;
     RECT  56.607 27.557 57.114 27.599 ;
     RECT  60.552 26.519 62.097 27.599 ;
     RECT  54.72 27.409 54.738 27.671 ;
     RECT  24.207 27.557 24.297 27.715 ;
     RECT  25.56 27.557 36.846 27.715 ;
     RECT  60.552 27.599 60.57 27.743 ;
     RECT  24.207 27.715 36.846 27.779 ;
     RECT  2.607 27.557 2.697 27.827 ;
     RECT  5.307 27.557 5.397 27.827 ;
     RECT  8.007 27.557 8.097 27.827 ;
     RECT  10.707 27.557 10.797 27.827 ;
     RECT  13.407 27.557 13.497 27.827 ;
     RECT  16.107 27.557 16.197 27.827 ;
     RECT  18.807 27.557 18.897 27.827 ;
     RECT  21.507 27.557 21.597 27.827 ;
     RECT  24.207 27.779 33.966 27.827 ;
     RECT  35.007 27.779 36.846 27.827 ;
     RECT  37.707 27.557 37.797 27.827 ;
     RECT  40.407 27.557 40.497 27.827 ;
     RECT  43.107 27.557 43.197 27.827 ;
     RECT  45.807 27.557 45.897 27.827 ;
     RECT  48.507 27.557 48.597 27.827 ;
     RECT  51.207 27.557 51.297 27.827 ;
     RECT  53.907 27.557 53.997 27.827 ;
     RECT  56.607 27.599 56.697 27.827 ;
     RECT  59.307 27.557 59.397 27.827 ;
     RECT  62.007 27.599 62.097 27.827 ;
     RECT  24.912 27.827 33.966 27.869 ;
     RECT  35.136 27.827 36.846 27.869 ;
     RECT  24.912 27.869 24.93 27.941 ;
     RECT  35.136 27.869 36.45 27.941 ;
     RECT  25.668 27.869 33.966 28.211 ;
     RECT  25.74 28.211 33.966 28.397 ;
     RECT  25.74 28.397 33.606 28.445 ;
     RECT  35.892 27.941 36.45 28.493 ;
     RECT  35.136 27.941 35.154 29.057 ;
     RECT  25.74 28.445 33.102 29.069 ;
     RECT  36.144 28.493 36.45 29.357 ;
     RECT  25.992 29.069 33.102 29.363 ;
     RECT  36.432 29.357 36.45 29.363 ;
     RECT  26.244 29.363 33.102 30.179 ;
     RECT  26.262 30.179 26.316 30.204 ;
     RECT  26.334 30.179 26.388 30.204 ;
     RECT  26.406 30.179 26.46 30.204 ;
     RECT  26.478 30.179 26.532 30.204 ;
     RECT  26.55 30.179 26.604 30.204 ;
     RECT  26.622 30.179 26.676 30.204 ;
     RECT  26.694 30.179 26.748 30.204 ;
     RECT  26.766 30.179 26.82 30.204 ;
     RECT  26.838 30.179 26.892 30.204 ;
     RECT  26.91 30.179 26.964 30.204 ;
     RECT  26.982 30.179 27.036 30.204 ;
     RECT  27.054 30.179 27.108 30.204 ;
     RECT  27.126 30.179 27.18 30.204 ;
     RECT  27.198 30.179 27.252 30.204 ;
     RECT  27.27 30.179 27.324 30.204 ;
     RECT  27.342 30.179 27.396 30.204 ;
     RECT  27.414 30.179 27.468 30.204 ;
     RECT  27.486 30.179 27.54 30.204 ;
     RECT  27.558 30.179 27.612 30.204 ;
     RECT  27.63 30.179 27.684 30.204 ;
     RECT  27.702 30.179 27.756 30.204 ;
     RECT  27.774 30.179 27.828 30.204 ;
     RECT  27.846 30.179 27.9 30.204 ;
     RECT  27.918 30.179 27.972 30.204 ;
     RECT  27.99 30.179 28.044 30.204 ;
     RECT  28.062 30.179 28.116 30.204 ;
     RECT  28.134 30.179 28.188 30.204 ;
     RECT  28.206 30.179 28.26 30.204 ;
     RECT  28.278 30.179 28.332 30.204 ;
     RECT  28.35 30.179 28.404 30.204 ;
     RECT  28.422 30.179 28.476 30.204 ;
     RECT  28.494 30.179 28.548 30.204 ;
     RECT  28.566 30.179 28.62 30.204 ;
     RECT  28.638 30.179 28.692 30.204 ;
     RECT  28.71 30.179 28.764 30.204 ;
     RECT  28.782 30.179 28.836 30.204 ;
     RECT  28.854 30.179 28.908 30.204 ;
     RECT  28.926 30.179 28.98 30.204 ;
     RECT  28.998 30.179 29.052 30.204 ;
     RECT  29.07 30.179 29.124 30.204 ;
     RECT  29.142 30.179 29.196 30.204 ;
     RECT  29.214 30.179 29.268 30.204 ;
     RECT  29.286 30.179 29.34 30.204 ;
     RECT  29.358 30.179 29.412 30.204 ;
     RECT  29.43 30.179 29.484 30.204 ;
     RECT  29.502 30.179 29.556 30.204 ;
     RECT  29.574 30.179 29.628 30.204 ;
     RECT  29.646 30.179 29.7 30.204 ;
     RECT  29.718 30.179 29.772 30.204 ;
     RECT  29.79 30.179 29.844 30.204 ;
     RECT  29.862 30.179 29.916 30.204 ;
     RECT  29.934 30.179 29.988 30.204 ;
     RECT  30.006 30.179 30.06 30.204 ;
     RECT  30.078 30.179 30.132 30.204 ;
     RECT  30.15 30.179 30.204 30.204 ;
     RECT  30.222 30.179 30.276 30.204 ;
     RECT  30.294 30.179 30.348 30.204 ;
     RECT  30.366 30.179 30.42 30.204 ;
     RECT  30.438 30.179 30.492 30.204 ;
     RECT  30.51 30.179 30.564 30.204 ;
     RECT  30.582 30.179 30.636 30.204 ;
     RECT  30.654 30.179 30.708 30.204 ;
     RECT  30.726 30.179 30.78 30.204 ;
     RECT  30.798 30.179 30.852 30.204 ;
     RECT  30.87 30.179 30.924 30.204 ;
     RECT  30.942 30.179 30.996 30.204 ;
     RECT  31.014 30.179 31.068 30.204 ;
     RECT  31.086 30.179 31.14 30.204 ;
     RECT  31.158 30.179 31.212 30.204 ;
     RECT  31.23 30.179 31.284 30.204 ;
     RECT  31.302 30.179 31.356 30.204 ;
     RECT  31.374 30.179 31.428 30.204 ;
     RECT  31.446 30.179 31.5 30.204 ;
     RECT  31.518 30.179 31.572 30.204 ;
     RECT  31.59 30.179 31.644 30.204 ;
     RECT  31.662 30.179 31.716 30.204 ;
     RECT  31.734 30.179 31.788 30.204 ;
     RECT  31.806 30.179 31.86 30.204 ;
     RECT  31.878 30.179 31.932 30.204 ;
     RECT  31.95 30.179 32.004 30.204 ;
     RECT  32.022 30.179 32.076 30.204 ;
     RECT  32.094 30.179 32.148 30.204 ;
     RECT  32.166 30.179 32.22 30.204 ;
     RECT  32.238 30.179 32.292 30.204 ;
     RECT  32.31 30.179 32.364 30.204 ;
     RECT  32.382 30.179 32.436 30.204 ;
     RECT  32.454 30.179 32.508 30.204 ;
     RECT  32.526 30.179 32.58 30.204 ;
     RECT  32.598 30.179 32.652 30.204 ;
     RECT  32.67 30.179 32.724 30.204 ;
     RECT  32.742 30.179 32.796 30.204 ;
     RECT  32.814 30.179 32.868 30.204 ;
     RECT  32.886 30.179 32.94 30.204 ;
     RECT  32.958 30.179 33.012 30.204 ;
     RECT  33.03 30.179 33.084 30.204 ;
    LAYER M4 ;
     RECT  0.037 15.6 0.06 15.624 ;
     RECT  0.084 15.312 0.179 15.336 ;
     RECT  0.06 15.336 0.179 15.408 ;
     RECT  0.084 15.408 0.179 15.432 ;
     RECT  0.06 15.432 0.179 15.624 ;
     RECT  0.179 15.312 2.329 15.336 ;
     RECT  2.329 15.312 2.408 15.48 ;
     RECT  0.037 22.032 2.408 22.056 ;
     RECT  2.408 2.148 2.512 27.552 ;
     RECT  2.512 2.418 2.6 27.552 ;
     RECT  2.6 2.418 2.704 27.822 ;
     RECT  2.704 15.456 5.108 15.48 ;
     RECT  2.704 22.032 5.108 22.056 ;
     RECT  5.108 2.148 5.212 27.552 ;
     RECT  5.212 2.418 5.3 27.552 ;
     RECT  5.3 2.418 5.404 27.822 ;
     RECT  5.404 15.456 7.808 15.48 ;
     RECT  5.404 22.032 7.808 22.056 ;
     RECT  7.808 2.148 7.912 27.552 ;
     RECT  7.912 2.418 8 27.552 ;
     RECT  8 2.418 8.104 27.822 ;
     RECT  8.104 15.456 10.508 15.48 ;
     RECT  8.104 22.032 10.508 22.056 ;
     RECT  10.508 2.148 10.612 27.552 ;
     RECT  10.612 2.418 10.7 27.552 ;
     RECT  10.7 2.418 10.804 27.822 ;
     RECT  10.804 15.456 13.208 15.48 ;
     RECT  10.804 22.032 13.208 22.056 ;
     RECT  13.208 2.148 13.312 27.552 ;
     RECT  13.312 2.418 13.4 27.552 ;
     RECT  13.4 2.418 13.504 27.822 ;
     RECT  13.504 15.456 15.908 15.48 ;
     RECT  13.504 22.032 15.908 22.056 ;
     RECT  15.908 2.148 16.012 27.552 ;
     RECT  16.012 2.418 16.1 27.552 ;
     RECT  16.1 2.418 16.204 27.822 ;
     RECT  16.204 15.456 18.608 15.48 ;
     RECT  16.204 22.032 18.608 22.056 ;
     RECT  18.608 2.148 18.712 27.552 ;
     RECT  18.712 2.418 18.8 27.552 ;
     RECT  18.8 2.418 18.904 27.822 ;
     RECT  18.904 15.456 21.308 15.48 ;
     RECT  18.904 22.032 21.308 22.056 ;
     RECT  21.308 2.148 21.412 27.552 ;
     RECT  21.412 2.418 21.5 27.552 ;
     RECT  21.5 2.418 21.604 27.822 ;
     RECT  21.604 15.456 24.008 15.48 ;
     RECT  21.604 22.032 24.008 22.056 ;
     RECT  24.008 2.148 24.112 27.552 ;
     RECT  24.112 2.418 24.2 27.552 ;
     RECT  24.2 2.418 24.304 27.822 ;
     RECT  25.585 27.6 25.657 27.624 ;
     RECT  25.657 27.072 25.693 27.624 ;
     RECT  24.304 25.68 25.837 25.704 ;
     RECT  25.693 26.784 25.837 27.624 ;
     RECT  25.585 24.48 26.161 24.504 ;
     RECT  26.161 24.48 26.305 24.648 ;
     RECT  24.304 22.032 26.437 22.056 ;
     RECT  26.305 23.856 26.437 24.648 ;
     RECT  24.304 15.456 26.708 15.48 ;
     RECT  26.437 22.032 26.708 24.648 ;
     RECT  25.837 25.68 26.708 27.624 ;
     RECT  26.708 2.148 26.812 27.624 ;
     RECT  26.812 2.418 26.9 27.624 ;
     RECT  26.9 2.418 27.004 27.822 ;
     RECT  25.729 29.04 27.209 29.064 ;
     RECT  27.004 25.44 27.353 27.384 ;
     RECT  27.349 30.144 27.497 30.168 ;
     RECT  27.353 26.256 27.605 27.384 ;
     RECT  27.925 29.088 28.213 29.112 ;
     RECT  27.004 22.032 28.321 24.072 ;
     RECT  27.605 26.544 28.465 27.384 ;
     RECT  28.213 29.088 28.501 29.64 ;
     RECT  28.465 26.544 28.604 27.96 ;
     RECT  28.321 22.032 28.609 24.696 ;
     RECT  28.609 21.504 28.645 24.696 ;
     RECT  28.645 21.168 29.113 24.792 ;
     RECT  28.604 26.208 29.113 27.96 ;
     RECT  29.113 21.168 29.221 27.96 ;
     RECT  29.221 20.976 29.257 28.056 ;
     RECT  28.501 29.088 29.257 30.168 ;
     RECT  29.257 20.976 29.297 30.168 ;
     RECT  29.365 14.112 29.408 14.136 ;
     RECT  29.149 17.472 29.408 17.496 ;
     RECT  29.297 20.976 29.408 29.688 ;
     RECT  29.408 2.148 29.512 29.688 ;
     RECT  29.512 2.418 29.704 29.688 ;
     RECT  29.704 16.848 29.909 18.792 ;
     RECT  29.704 21.168 29.939 29.688 ;
     RECT  29.939 23.904 30.301 29.688 ;
     RECT  29.939 21.168 30.341 22.824 ;
     RECT  30.301 23.904 30.449 30.072 ;
     RECT  30.449 24.24 30.469 30.072 ;
     RECT  30.469 24.24 30.611 30.12 ;
     RECT  30.611 24.24 30.707 28.776 ;
     RECT  29.704 13.008 30.769 13.992 ;
     RECT  30.611 29.904 30.917 30.12 ;
     RECT  30.769 12.864 31.165 13.992 ;
     RECT  29.909 16.848 31.237 18.504 ;
     RECT  30.917 30 31.475 30.12 ;
     RECT  30.707 24.24 31.717 27.384 ;
     RECT  30.707 28.368 31.717 28.776 ;
     RECT  31.717 24.24 31.909 28.776 ;
     RECT  31.475 30 31.909 30.072 ;
     RECT  31.909 24.24 31.957 30.072 ;
     RECT  31.165 12.864 32.108 14.232 ;
     RECT  31.237 16.848 32.108 19.08 ;
     RECT  30.341 21.168 32.108 22.776 ;
     RECT  31.957 24.192 32.108 30.072 ;
     RECT  32.108 2.148 32.212 30.072 ;
     RECT  32.212 2.418 32.339 30.072 ;
     RECT  32.339 2.418 32.404 29.352 ;
     RECT  32.404 21.168 32.429 22.248 ;
     RECT  32.429 21.168 32.537 22.2 ;
     RECT  32.404 23.376 33.365 29.352 ;
     RECT  32.404 12.864 33.397 15.48 ;
     RECT  32.537 22.032 33.932 22.2 ;
     RECT  33.397 12.864 34.369 15.768 ;
     RECT  32.404 7.344 34.808 7.368 ;
     RECT  32.404 10.128 34.808 11.496 ;
     RECT  34.369 12.864 34.808 15.864 ;
     RECT  32.404 16.848 34.808 19.08 ;
     RECT  33.932 22.032 34.808 22.344 ;
     RECT  33.365 23.856 34.808 29.352 ;
     RECT  34.808 2.148 34.912 29.352 ;
     RECT  34.912 2.418 35.104 29.352 ;
     RECT  35.104 26.016 35.561 29.352 ;
     RECT  35.104 21.12 35.644 21.144 ;
     RECT  35.561 26.016 35.669 27.144 ;
     RECT  35.669 26.208 35.885 27.144 ;
     RECT  35.885 26.208 35.921 26.664 ;
     RECT  35.561 28.464 35.921 29.352 ;
     RECT  35.921 26.208 36.029 26.568 ;
     RECT  36.029 26.448 36.101 26.568 ;
     RECT  35.104 16.848 36.133 19.08 ;
     RECT  36.101 26.448 36.137 26.472 ;
     RECT  35.921 28.752 36.173 29.352 ;
     RECT  35.104 23.328 36.179 23.352 ;
     RECT  36.173 28.752 36.389 28.776 ;
     RECT  35.104 12.864 36.817 15.864 ;
     RECT  35.104 7.344 37.508 7.368 ;
     RECT  35.104 10.128 37.508 11.496 ;
     RECT  36.817 12.72 37.508 15.864 ;
     RECT  36.133 16.848 37.508 19.656 ;
     RECT  37.508 2.148 37.612 27.552 ;
     RECT  37.612 2.418 37.7 27.552 ;
     RECT  37.7 2.418 37.804 27.822 ;
     RECT  37.804 7.344 40.208 7.368 ;
     RECT  37.804 10.128 40.208 11.496 ;
     RECT  37.804 12.864 40.208 15.864 ;
     RECT  37.804 16.848 40.208 19.656 ;
     RECT  40.208 2.148 40.312 27.552 ;
     RECT  40.312 2.418 40.4 27.552 ;
     RECT  40.4 2.418 40.504 27.822 ;
     RECT  40.504 7.344 42.908 7.368 ;
     RECT  40.504 10.128 42.908 11.496 ;
     RECT  40.504 12.864 42.908 15.864 ;
     RECT  40.504 16.848 42.908 19.656 ;
     RECT  42.908 2.148 43.012 27.552 ;
     RECT  43.012 2.418 43.1 27.552 ;
     RECT  43.1 2.418 43.204 27.822 ;
     RECT  43.204 7.344 45.608 7.368 ;
     RECT  43.204 10.128 45.608 11.496 ;
     RECT  43.204 12.864 45.608 15.864 ;
     RECT  43.204 16.848 45.608 19.656 ;
     RECT  45.608 2.148 45.712 27.552 ;
     RECT  45.712 2.418 45.8 27.552 ;
     RECT  45.8 2.418 45.904 27.822 ;
     RECT  45.904 7.344 48.308 7.368 ;
     RECT  45.904 10.128 48.308 11.496 ;
     RECT  45.904 12.864 48.308 15.864 ;
     RECT  45.904 16.848 48.308 19.656 ;
     RECT  48.308 2.148 48.412 27.552 ;
     RECT  48.412 2.418 48.5 27.552 ;
     RECT  48.5 2.418 48.604 27.822 ;
     RECT  48.604 7.344 51.008 7.368 ;
     RECT  48.604 10.128 51.008 11.496 ;
     RECT  48.604 12.864 51.008 15.864 ;
     RECT  48.604 16.848 51.008 19.656 ;
     RECT  51.008 2.148 51.112 27.552 ;
     RECT  51.112 2.418 51.2 27.552 ;
     RECT  51.2 2.418 51.304 27.822 ;
     RECT  51.304 7.344 53.708 7.368 ;
     RECT  51.304 10.128 53.708 11.496 ;
     RECT  51.304 12.864 53.708 15.864 ;
     RECT  51.304 16.848 53.708 19.656 ;
     RECT  53.708 2.148 53.812 27.552 ;
     RECT  53.812 2.418 53.9 27.552 ;
     RECT  53.9 2.418 54.004 27.822 ;
     RECT  54.004 7.344 56.408 7.368 ;
     RECT  54.004 10.128 56.408 11.496 ;
     RECT  54.004 12.864 56.408 15.864 ;
     RECT  54.004 16.848 56.408 19.656 ;
     RECT  56.408 2.148 56.512 27.552 ;
     RECT  56.512 2.418 56.6 27.552 ;
     RECT  56.6 2.418 56.704 27.822 ;
     RECT  56.704 7.344 59.108 7.368 ;
     RECT  56.704 10.128 59.108 11.496 ;
     RECT  56.704 12.864 59.108 15.864 ;
     RECT  56.704 16.848 59.108 19.656 ;
     RECT  59.108 2.148 59.212 27.552 ;
     RECT  59.212 2.418 59.3 27.552 ;
     RECT  59.3 2.418 59.404 27.822 ;
     RECT  59.404 16.848 60.113 19.656 ;
     RECT  59.404 9.504 61.513 11.496 ;
     RECT  59.404 12.864 61.513 15.864 ;
     RECT  59.404 7.344 61.549 7.368 ;
     RECT  61.549 7.344 61.808 8.232 ;
     RECT  61.513 9.312 61.808 11.496 ;
     RECT  61.513 12.528 61.808 15.864 ;
     RECT  60.113 16.848 61.808 19.08 ;
     RECT  61.808 2.148 61.912 27.552 ;
     RECT  61.912 2.418 62 27.552 ;
     RECT  62 2.418 62.104 27.822 ;
     RECT  62.104 6.864 63.277 19.08 ;
     RECT  63.277 6.864 64.692 6.888 ;
     RECT  63.277 6.888 64.716 6.96 ;
     RECT  63.277 6.96 64.692 6.984 ;
     RECT  63.277 6.984 64.716 7.056 ;
     RECT  63.277 7.056 64.692 7.08 ;
     RECT  63.277 7.08 64.716 7.152 ;
     RECT  63.277 7.152 64.692 7.176 ;
     RECT  63.277 7.176 64.716 7.248 ;
     RECT  63.277 7.248 64.692 7.272 ;
     RECT  63.277 7.272 64.716 7.344 ;
     RECT  63.277 7.344 64.692 7.368 ;
     RECT  63.277 7.368 64.716 7.44 ;
     RECT  63.277 7.44 64.692 7.464 ;
     RECT  63.277 7.464 64.716 7.536 ;
     RECT  63.277 7.536 64.692 7.56 ;
     RECT  63.277 7.56 64.716 7.632 ;
     RECT  63.277 7.632 64.692 7.656 ;
     RECT  63.277 7.656 64.716 7.728 ;
     RECT  63.277 7.728 64.692 7.752 ;
     RECT  63.277 7.752 64.716 7.824 ;
     RECT  63.277 7.824 64.692 7.848 ;
     RECT  63.277 7.848 64.716 7.92 ;
     RECT  63.277 7.92 64.692 7.944 ;
     RECT  63.277 7.944 64.716 8.016 ;
     RECT  63.277 8.016 64.692 8.04 ;
     RECT  63.277 8.04 64.716 8.112 ;
     RECT  63.277 8.112 64.692 8.136 ;
     RECT  63.277 8.136 64.716 8.208 ;
     RECT  63.277 8.208 64.692 8.232 ;
     RECT  63.277 8.232 64.716 8.304 ;
     RECT  63.277 8.304 64.692 8.328 ;
     RECT  63.277 8.328 64.716 8.4 ;
     RECT  63.277 8.4 64.692 8.424 ;
     RECT  63.277 8.424 64.716 8.496 ;
     RECT  63.277 8.496 64.692 8.52 ;
     RECT  63.277 8.52 64.716 8.592 ;
     RECT  63.277 8.592 64.692 8.616 ;
     RECT  63.277 8.616 64.716 8.688 ;
     RECT  63.277 8.688 64.692 8.712 ;
     RECT  63.277 8.712 64.716 8.784 ;
     RECT  63.277 8.784 64.692 8.808 ;
     RECT  63.277 8.808 64.716 8.88 ;
     RECT  63.277 8.88 64.692 8.904 ;
     RECT  63.277 8.904 64.716 8.976 ;
     RECT  63.277 8.976 64.692 9 ;
     RECT  63.277 9 64.716 9.072 ;
     RECT  63.277 9.072 64.692 9.096 ;
     RECT  63.277 9.096 64.716 9.168 ;
     RECT  63.277 9.168 64.692 9.192 ;
     RECT  63.277 9.192 64.716 9.264 ;
     RECT  63.277 9.264 64.692 9.288 ;
     RECT  63.277 9.288 64.716 9.36 ;
     RECT  63.277 9.36 64.692 9.384 ;
     RECT  63.277 9.384 64.716 9.456 ;
     RECT  63.277 9.456 64.692 9.48 ;
     RECT  63.277 9.48 64.716 9.552 ;
     RECT  63.277 9.552 64.692 9.576 ;
     RECT  63.277 9.576 64.716 9.648 ;
     RECT  63.277 9.648 64.692 9.672 ;
     RECT  63.277 9.672 64.716 9.744 ;
     RECT  63.277 9.744 64.692 9.768 ;
     RECT  63.277 9.768 64.716 9.84 ;
     RECT  63.277 9.84 64.692 9.864 ;
     RECT  63.277 9.864 64.716 9.936 ;
     RECT  63.277 9.936 64.692 9.96 ;
     RECT  63.277 9.96 64.716 10.032 ;
     RECT  63.277 10.032 64.692 10.056 ;
     RECT  63.277 10.056 64.716 10.128 ;
     RECT  63.277 10.128 64.692 10.152 ;
     RECT  63.277 10.152 64.716 10.224 ;
     RECT  63.277 10.224 64.692 10.248 ;
     RECT  63.277 10.248 64.716 10.32 ;
     RECT  63.277 10.32 64.692 10.344 ;
     RECT  63.277 10.344 64.716 10.416 ;
     RECT  63.277 10.416 64.692 10.44 ;
     RECT  63.277 10.44 64.716 10.512 ;
     RECT  63.277 10.512 64.692 10.536 ;
     RECT  63.277 10.536 64.716 10.608 ;
     RECT  63.277 10.608 64.692 10.632 ;
     RECT  63.277 10.632 64.716 10.704 ;
     RECT  63.277 10.704 64.692 10.728 ;
     RECT  63.277 10.728 64.716 10.8 ;
     RECT  63.277 10.8 64.692 10.824 ;
     RECT  63.277 10.824 64.716 10.896 ;
     RECT  63.277 10.896 64.692 10.92 ;
     RECT  63.277 10.92 64.716 10.992 ;
     RECT  63.277 10.992 64.692 11.016 ;
     RECT  63.277 11.016 64.716 11.088 ;
     RECT  63.277 11.088 64.692 11.112 ;
     RECT  63.277 11.112 64.716 11.184 ;
     RECT  63.277 11.184 64.692 11.208 ;
     RECT  63.277 11.208 64.716 11.28 ;
     RECT  63.277 11.28 64.692 11.304 ;
     RECT  63.277 11.304 64.716 11.376 ;
     RECT  63.277 11.376 64.692 11.4 ;
     RECT  63.277 11.4 64.716 11.472 ;
     RECT  63.277 11.472 64.692 11.496 ;
     RECT  63.277 11.496 64.716 11.568 ;
     RECT  63.277 11.568 64.692 11.592 ;
     RECT  63.277 11.592 64.716 11.664 ;
     RECT  63.277 11.664 64.692 11.688 ;
     RECT  63.277 11.688 64.716 11.76 ;
     RECT  63.277 11.76 64.692 11.784 ;
     RECT  63.277 11.784 64.716 11.856 ;
     RECT  63.277 11.856 64.692 11.88 ;
     RECT  63.277 11.88 64.716 11.952 ;
     RECT  63.277 11.952 64.692 11.976 ;
     RECT  63.277 11.976 64.716 12.048 ;
     RECT  63.277 12.048 64.692 12.072 ;
     RECT  63.277 12.072 64.716 12.144 ;
     RECT  63.277 12.144 64.692 12.168 ;
     RECT  63.277 12.168 64.716 12.24 ;
     RECT  63.277 12.24 64.692 12.264 ;
     RECT  63.277 12.264 64.716 12.336 ;
     RECT  63.277 12.336 64.692 12.36 ;
     RECT  63.277 12.36 64.716 12.432 ;
     RECT  63.277 12.432 64.692 12.456 ;
     RECT  63.277 12.456 64.716 12.528 ;
     RECT  63.277 12.528 64.692 12.552 ;
     RECT  63.277 12.552 64.716 12.624 ;
     RECT  63.277 12.624 64.692 12.648 ;
     RECT  63.277 12.648 64.716 12.72 ;
     RECT  63.277 12.72 64.692 12.744 ;
     RECT  63.277 12.744 64.716 12.816 ;
     RECT  63.277 12.816 64.692 12.84 ;
     RECT  63.277 12.84 64.716 12.912 ;
     RECT  63.277 12.912 64.692 12.936 ;
     RECT  63.277 12.936 64.716 13.008 ;
     RECT  63.277 13.008 64.692 13.032 ;
     RECT  63.277 13.032 64.716 13.104 ;
     RECT  63.277 13.104 64.692 13.128 ;
     RECT  63.277 13.128 64.716 13.2 ;
     RECT  63.277 13.2 64.692 13.224 ;
     RECT  63.277 13.224 64.716 13.296 ;
     RECT  63.277 13.296 64.692 13.32 ;
     RECT  63.277 13.32 64.716 13.392 ;
     RECT  63.277 13.392 64.692 13.416 ;
     RECT  63.277 13.416 64.716 13.488 ;
     RECT  63.277 13.488 64.692 13.512 ;
     RECT  63.277 13.512 64.716 13.584 ;
     RECT  63.277 13.584 64.692 13.608 ;
     RECT  63.277 13.608 64.716 13.68 ;
     RECT  63.277 13.68 64.692 13.704 ;
     RECT  63.277 13.704 64.716 13.776 ;
     RECT  63.277 13.776 64.692 13.8 ;
     RECT  63.277 13.8 64.716 13.872 ;
     RECT  63.277 13.872 64.692 13.896 ;
     RECT  63.277 13.896 64.716 13.968 ;
     RECT  63.277 13.968 64.692 13.992 ;
     RECT  63.277 13.992 64.716 14.064 ;
     RECT  63.277 14.064 64.692 14.088 ;
     RECT  63.277 14.088 64.716 14.16 ;
     RECT  63.277 14.16 64.692 14.184 ;
     RECT  63.277 14.184 64.716 14.256 ;
     RECT  63.277 14.256 64.692 14.28 ;
     RECT  63.277 14.28 64.716 14.352 ;
     RECT  63.277 14.352 64.692 14.376 ;
     RECT  63.277 14.376 64.716 14.448 ;
     RECT  63.277 14.448 64.692 14.472 ;
     RECT  63.277 14.472 64.716 14.544 ;
     RECT  63.277 14.544 64.692 14.568 ;
     RECT  63.277 14.568 64.716 14.64 ;
     RECT  63.277 14.64 64.692 14.664 ;
     RECT  63.277 14.664 64.716 14.736 ;
     RECT  63.277 14.736 64.692 14.76 ;
     RECT  63.277 14.76 64.716 14.832 ;
     RECT  63.277 14.832 64.692 14.856 ;
     RECT  63.277 14.856 64.716 14.928 ;
     RECT  63.277 14.928 64.692 14.952 ;
     RECT  63.277 14.952 64.716 15.024 ;
     RECT  63.277 15.024 64.692 15.048 ;
     RECT  63.277 15.048 64.716 15.12 ;
     RECT  63.277 15.12 64.692 15.144 ;
     RECT  63.277 15.144 64.716 15.216 ;
     RECT  63.277 15.216 64.692 15.24 ;
     RECT  63.277 15.24 64.716 15.312 ;
     RECT  63.277 15.312 64.692 15.336 ;
     RECT  63.277 15.336 64.716 15.408 ;
     RECT  63.277 15.408 64.692 15.432 ;
     RECT  63.277 15.432 64.716 15.504 ;
     RECT  63.277 15.504 64.692 15.528 ;
     RECT  63.277 15.528 64.716 15.6 ;
     RECT  63.277 15.6 64.692 15.624 ;
     RECT  63.277 15.624 64.716 15.696 ;
     RECT  63.277 15.696 64.692 15.72 ;
     RECT  63.277 15.72 64.716 15.792 ;
     RECT  63.277 15.792 64.692 15.816 ;
     RECT  63.277 15.816 64.716 15.888 ;
     RECT  63.277 15.888 64.692 15.912 ;
     RECT  63.277 15.912 64.716 15.984 ;
     RECT  63.277 15.984 64.692 16.008 ;
     RECT  63.277 16.008 64.716 16.08 ;
     RECT  63.277 16.08 64.692 16.104 ;
     RECT  63.277 16.104 64.716 16.176 ;
     RECT  63.277 16.176 64.692 16.2 ;
     RECT  63.277 16.2 64.716 16.272 ;
     RECT  63.277 16.272 64.692 16.296 ;
     RECT  63.277 16.296 64.716 16.368 ;
     RECT  63.277 16.368 64.692 16.392 ;
     RECT  63.277 16.392 64.716 16.464 ;
     RECT  63.277 16.464 64.692 16.488 ;
     RECT  63.277 16.488 64.716 16.56 ;
     RECT  63.277 16.56 64.692 16.584 ;
     RECT  63.277 16.584 64.716 16.656 ;
     RECT  63.277 16.656 64.692 16.68 ;
     RECT  63.277 16.68 64.716 16.752 ;
     RECT  63.277 16.752 64.692 16.776 ;
     RECT  63.277 16.776 64.716 16.848 ;
     RECT  63.277 16.848 64.692 16.872 ;
     RECT  63.277 16.872 64.716 16.944 ;
     RECT  63.277 16.944 64.692 16.968 ;
     RECT  63.277 16.968 64.716 17.04 ;
     RECT  63.277 17.04 64.692 17.064 ;
     RECT  63.277 17.064 64.716 17.136 ;
     RECT  63.277 17.136 64.692 17.16 ;
     RECT  63.277 17.16 64.716 17.232 ;
     RECT  63.277 17.232 64.692 17.256 ;
     RECT  63.277 17.256 64.716 17.328 ;
     RECT  63.277 17.328 64.692 17.352 ;
     RECT  63.277 17.352 64.716 17.424 ;
     RECT  63.277 17.424 64.692 17.448 ;
     RECT  63.277 17.448 64.716 17.52 ;
     RECT  63.277 17.52 64.692 17.544 ;
     RECT  63.277 17.544 64.716 17.616 ;
     RECT  63.277 17.616 64.692 17.64 ;
     RECT  63.277 17.64 64.716 17.712 ;
     RECT  63.277 17.712 64.692 17.736 ;
     RECT  63.277 17.736 64.716 17.808 ;
     RECT  63.277 17.808 64.692 17.832 ;
     RECT  63.277 17.832 64.716 17.904 ;
     RECT  63.277 17.904 64.692 17.928 ;
     RECT  63.277 17.928 64.716 18 ;
     RECT  63.277 18 64.692 18.024 ;
     RECT  63.277 18.024 64.716 18.096 ;
     RECT  63.277 18.096 64.692 18.12 ;
     RECT  63.277 18.12 64.716 18.192 ;
     RECT  63.277 18.192 64.692 18.216 ;
     RECT  63.277 18.216 64.716 18.288 ;
     RECT  63.277 18.288 64.692 18.312 ;
     RECT  63.277 18.312 64.716 18.384 ;
     RECT  63.277 18.384 64.692 18.408 ;
     RECT  63.277 18.408 64.716 18.48 ;
     RECT  63.277 18.48 64.692 18.504 ;
     RECT  63.277 18.504 64.716 18.576 ;
     RECT  63.277 18.576 64.692 18.6 ;
     RECT  63.277 18.6 64.716 18.672 ;
     RECT  63.277 18.672 64.692 18.696 ;
     RECT  63.277 18.696 64.716 18.768 ;
     RECT  63.277 18.768 64.692 18.792 ;
     RECT  63.277 18.792 64.716 18.864 ;
     RECT  63.277 18.864 64.692 18.888 ;
     RECT  63.277 18.888 64.716 18.96 ;
     RECT  63.277 18.96 64.692 18.984 ;
     RECT  63.277 18.984 64.716 19.056 ;
     RECT  63.277 19.056 64.692 19.08 ;
     RECT  63.277 19.08 64.716 19.152 ;
     RECT  63.277 19.152 64.692 19.176 ;
     RECT  64.716 9.504 64.757 9.528 ;
     RECT  64.716 13.536 64.757 13.584 ;
     RECT  64.716 13.608 64.757 13.68 ;
     RECT  64.716 13.704 64.757 13.776 ;
     RECT  64.716 13.8 64.757 13.872 ;
     RECT  64.716 13.896 64.757 13.968 ;
     RECT  64.716 13.992 64.757 14.064 ;
     RECT  64.716 14.088 64.757 14.136 ;
     RECT  64.716 15.456 64.757 15.504 ;
     RECT  64.716 15.528 64.757 15.6 ;
     RECT  64.716 15.624 64.757 15.696 ;
     RECT  64.716 15.72 64.757 15.792 ;
     RECT  64.716 15.816 64.757 15.864 ;
     RECT  64.716 17.76 64.757 17.784 ;
    LAYER M5 ;
     RECT  2.4 2.137 2.52 2.151 ;
     RECT  5.1 2.137 5.22 2.151 ;
     RECT  7.8 2.137 7.92 2.151 ;
     RECT  10.5 2.137 10.62 2.151 ;
     RECT  13.2 2.137 13.32 2.151 ;
     RECT  15.9 2.137 16.02 2.151 ;
     RECT  18.6 2.137 18.72 2.151 ;
     RECT  21.3 2.137 21.42 2.151 ;
     RECT  24 2.137 24.12 2.151 ;
     RECT  26.7 2.137 26.82 2.151 ;
     RECT  29.4 2.137 29.52 2.151 ;
     RECT  32.1 2.137 32.22 2.151 ;
     RECT  34.8 2.137 34.92 2.151 ;
     RECT  37.5 2.137 37.62 2.151 ;
     RECT  40.2 2.137 40.32 2.151 ;
     RECT  42.9 2.137 43.02 2.151 ;
     RECT  45.6 2.137 45.72 2.151 ;
     RECT  48.3 2.137 48.42 2.151 ;
     RECT  51 2.137 51.12 2.151 ;
     RECT  53.7 2.137 53.82 2.151 ;
     RECT  56.4 2.137 56.52 2.151 ;
     RECT  59.1 2.137 59.22 2.151 ;
     RECT  61.8 2.137 61.92 2.151 ;
     RECT  26.7 2.151 27.012 15.445 ;
     RECT  61.8 2.151 62.112 15.541 ;
     RECT  0.144 15.397 0.168 15.589 ;
     RECT  0.048 15.589 0.168 15.635 ;
     RECT  61.8 15.541 62.664 15.827 ;
     RECT  29.4 2.151 29.712 18.757 ;
     RECT  29.4 18.757 29.88 20.965 ;
     RECT  34.8 2.151 35.112 21.109 ;
     RECT  36.144 19.621 36.168 21.109 ;
     RECT  32.1 2.151 32.412 21.301 ;
     RECT  29.232 20.965 29.88 21.637 ;
     RECT  34.8 21.109 36.168 22.021 ;
     RECT  0.048 15.635 0.072 22.067 ;
     RECT  31.2 21.301 32.412 22.213 ;
     RECT  26.448 15.445 27.012 22.789 ;
     RECT  29.232 21.637 29.976 22.789 ;
     RECT  33.984 22.021 36.168 23.363 ;
     RECT  26.448 22.789 29.976 23.891 ;
     RECT  33.984 23.363 35.592 23.891 ;
     RECT  28.464 23.891 29.976 23.893 ;
     RECT  31.056 22.213 32.412 23.893 ;
     RECT  28.464 23.893 32.412 24.083 ;
     RECT  28.656 24.083 32.412 24.517 ;
     RECT  26.448 23.891 27.144 24.659 ;
     RECT  26.7 24.659 27.144 25.571 ;
     RECT  34.032 23.891 35.592 25.715 ;
     RECT  28.656 24.517 32.52 26.243 ;
     RECT  2.4 2.151 2.712 27.819 ;
     RECT  5.1 2.151 5.412 27.819 ;
     RECT  7.8 2.151 8.112 27.819 ;
     RECT  10.5 2.151 10.812 27.819 ;
     RECT  13.2 2.151 13.512 27.819 ;
     RECT  15.9 2.151 16.212 27.819 ;
     RECT  18.6 2.151 18.912 27.819 ;
     RECT  21.3 2.151 21.612 27.819 ;
     RECT  24 2.151 24.312 27.819 ;
     RECT  26.7 25.571 27.012 27.819 ;
     RECT  29.4 26.243 32.52 27.819 ;
     RECT  34.8 25.715 35.592 27.819 ;
     RECT  37.5 2.151 37.812 27.819 ;
     RECT  40.2 2.151 40.512 27.819 ;
     RECT  42.9 2.151 43.212 27.819 ;
     RECT  45.6 2.151 45.912 27.819 ;
     RECT  48.3 2.151 48.612 27.819 ;
     RECT  51 2.151 51.312 27.819 ;
     RECT  53.7 2.151 54.012 27.819 ;
     RECT  56.4 2.151 56.712 27.819 ;
     RECT  59.1 2.151 59.412 27.819 ;
     RECT  61.8 15.827 62.112 27.819 ;
     RECT  2.592 27.819 2.712 27.833 ;
     RECT  5.292 27.819 5.412 27.833 ;
     RECT  7.992 27.819 8.112 27.833 ;
     RECT  10.692 27.819 10.812 27.833 ;
     RECT  13.392 27.819 13.512 27.833 ;
     RECT  16.092 27.819 16.212 27.833 ;
     RECT  18.792 27.819 18.912 27.833 ;
     RECT  21.492 27.819 21.612 27.833 ;
     RECT  24.192 27.819 24.312 27.833 ;
     RECT  26.892 27.819 27.012 27.833 ;
     RECT  34.992 27.819 35.592 27.833 ;
     RECT  37.692 27.819 37.812 27.833 ;
     RECT  40.392 27.819 40.512 27.833 ;
     RECT  43.092 27.819 43.212 27.833 ;
     RECT  45.792 27.819 45.912 27.833 ;
     RECT  48.492 27.819 48.612 27.833 ;
     RECT  51.192 27.819 51.312 27.833 ;
     RECT  53.892 27.819 54.012 27.833 ;
     RECT  56.592 27.819 56.712 27.833 ;
     RECT  59.292 27.819 59.412 27.833 ;
     RECT  61.992 27.819 62.112 27.833 ;
     RECT  29.52 27.819 32.52 30.132 ;
     RECT  29.544 30.132 29.616 30.16 ;
     RECT  29.64 30.132 29.712 30.16 ;
     RECT  29.736 30.132 29.808 30.16 ;
     RECT  29.832 30.132 29.904 30.16 ;
     RECT  29.928 30.132 30 30.16 ;
     RECT  30.024 30.132 30.096 30.16 ;
     RECT  30.12 30.132 30.192 30.16 ;
     RECT  30.216 30.132 30.288 30.16 ;
     RECT  30.312 30.132 30.384 30.16 ;
     RECT  30.408 30.132 30.48 30.16 ;
     RECT  30.504 30.132 30.576 30.16 ;
     RECT  30.6 30.132 30.672 30.16 ;
     RECT  30.696 30.132 30.768 30.16 ;
     RECT  30.792 30.132 30.864 30.16 ;
     RECT  30.888 30.132 30.96 30.16 ;
     RECT  30.984 30.132 31.056 30.16 ;
     RECT  31.08 30.132 31.152 30.16 ;
     RECT  31.176 30.132 31.248 30.16 ;
     RECT  31.272 30.132 31.344 30.16 ;
     RECT  31.368 30.132 31.44 30.16 ;
     RECT  31.464 30.132 31.536 30.16 ;
     RECT  31.56 30.132 31.632 30.16 ;
     RECT  31.656 30.132 31.728 30.16 ;
     RECT  31.752 30.132 31.824 30.16 ;
     RECT  31.848 30.132 31.92 30.16 ;
     RECT  31.944 30.132 32.016 30.16 ;
     RECT  32.04 30.132 32.112 30.16 ;
     RECT  32.136 30.132 32.208 30.16 ;
     RECT  32.232 30.132 32.304 30.16 ;
     RECT  32.328 30.132 32.4 30.16 ;
     RECT  32.424 30.132 32.496 30.16 ;
     RECT  35.112 19.621 36.144 21.109 ;
     RECT  36.168 19.621 37.5 23.363 ;
     RECT  29.88 21.301 31.2 21.637 ;
     RECT  29.976 21.637 31.2 22.213 ;
     RECT  29.976 22.213 31.056 23.893 ;
     RECT  27.144 23.891 28.464 24.083 ;
     RECT  33.984 23.891 34.032 24.517 ;
     RECT  27.144 24.083 28.656 25.571 ;
     RECT  32.52 24.517 34.032 25.715 ;
  END
END qfd_rlyh_128_NE_65x30
END LIBRARY
